# Copyright lowRISC contributors (OpenTitan project).
# Licensed under the Apache License, Version 2.0, see LICENSE for details.
# SPDX-License-Identifier: Apache-2.0
#
# This file was derived by lowRISC contributors (OpenTitan project) from the
# IHP Open PDK SRAM abstract RM_IHPSG13_1P_8192x32_c4.lef
# (https://github.com/IHP-GmbH/IHP-Open-PDK, ihp-sg13g2/libs.ref/sg13g2_sram/lef).
# It is a synthetic abstract, not an IHP release: the macro size and pins come
# from the Liberty view, the pin shapes, power straps and antenna values from
# the IHP abstract. IHP's original notice follows:
#
#   Copyright 2023 IHP PDK Authors
#
#   Licensed under the Apache License, Version 2.0 (the "License");
#   you may not use this file except in compliance with the License.
#   You may obtain a copy of the License at
#
#      https://www.apache.org/licenses/LICENSE-2.0
#
#   Unless required by applicable law or agreed to in writing, software
#   distributed under the License is distributed on an "AS IS" BASIS,
#   WITHOUT WARRANTIES OR CONDITIONS OF ANY KIND, either express or implied.
#   See the License for the specific language governing permissions and
#   limitations under the License.
#
#   Generated on Mon Apr  7 14:15:46 2025
#
# Generated by gen_synthetic_lef.py from the Liberty view. Do not edit.
# Synthetic abstract: no physical layout exists behind this macro.

VERSION 5.7 ;
BUSBITCHARS "[]" ;
DIVIDERCHAR "/" ;

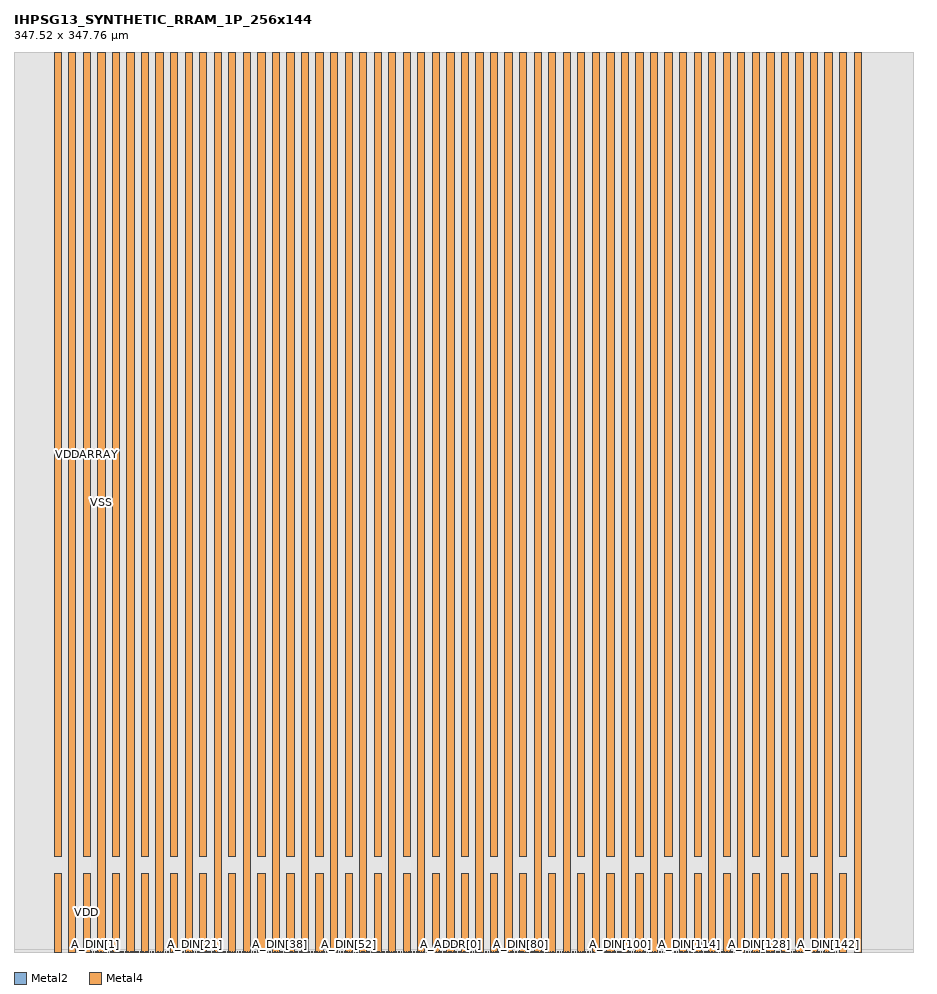
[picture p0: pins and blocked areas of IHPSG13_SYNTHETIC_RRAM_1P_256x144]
MACRO IHPSG13_SYNTHETIC_RRAM_1P_256x144
  CLASS BLOCK ;
  ORIGIN 0 0 ;
  FOREIGN IHPSG13_SYNTHETIC_RRAM_1P_256x144 0 0 ;
  SIZE 347.52 BY 347.76 ;
  SYMMETRY X Y R90 ;
  PIN A_DIN[0]
    DIRECTION INPUT ;
    USE SIGNAL ;
    ANTENNAMODEL OXIDE1 ;
      ANTENNAGATEAREA 0.20085 LAYER Metal2 ;
    PORT
      LAYER Metal2 ;
        RECT 29.63 0 29.89 0.26 ;
    END
  END A_DIN[0]
  PIN A_DOUT[0]
    DIRECTION OUTPUT ;
    USE SIGNAL ;
    ANTENNADIFFAREA 0.988 LAYER Metal2 ;
    PORT
      LAYER Metal2 ;
        RECT 30.59 0 30.85 0.26 ;
    END
  END A_DOUT[0]
  PIN A_DIN[1]
    DIRECTION INPUT ;
    USE SIGNAL ;
    ANTENNAMODEL OXIDE1 ;
      ANTENNAGATEAREA 0.20085 LAYER Metal2 ;
    PORT
      LAYER Metal2 ;
        RECT 31.55 0 31.81 0.26 ;
    END
  END A_DIN[1]
  PIN A_DOUT[1]
    DIRECTION OUTPUT ;
    USE SIGNAL ;
    ANTENNADIFFAREA 0.988 LAYER Metal2 ;
    PORT
      LAYER Metal2 ;
        RECT 32.51 0 32.77 0.26 ;
    END
  END A_DOUT[1]
  PIN A_DIN[2]
    DIRECTION INPUT ;
    USE SIGNAL ;
    ANTENNAMODEL OXIDE1 ;
      ANTENNAGATEAREA 0.20085 LAYER Metal2 ;
    PORT
      LAYER Metal2 ;
        RECT 33.47 0 33.73 0.26 ;
    END
  END A_DIN[2]
  PIN A_DOUT[2]
    DIRECTION OUTPUT ;
    USE SIGNAL ;
    ANTENNADIFFAREA 0.988 LAYER Metal2 ;
    PORT
      LAYER Metal2 ;
        RECT 34.43 0 34.69 0.26 ;
    END
  END A_DOUT[2]
  PIN A_DIN[3]
    DIRECTION INPUT ;
    USE SIGNAL ;
    ANTENNAMODEL OXIDE1 ;
      ANTENNAGATEAREA 0.20085 LAYER Metal2 ;
    PORT
      LAYER Metal2 ;
        RECT 35.39 0 35.65 0.26 ;
    END
  END A_DIN[3]
  PIN A_DOUT[3]
    DIRECTION OUTPUT ;
    USE SIGNAL ;
    ANTENNADIFFAREA 0.988 LAYER Metal2 ;
    PORT
      LAYER Metal2 ;
        RECT 36.35 0 36.61 0.26 ;
    END
  END A_DOUT[3]
  PIN A_DIN[4]
    DIRECTION INPUT ;
    USE SIGNAL ;
    ANTENNAMODEL OXIDE1 ;
      ANTENNAGATEAREA 0.20085 LAYER Metal2 ;
    PORT
      LAYER Metal2 ;
        RECT 37.31 0 37.57 0.26 ;
    END
  END A_DIN[4]
  PIN A_DOUT[4]
    DIRECTION OUTPUT ;
    USE SIGNAL ;
    ANTENNADIFFAREA 0.988 LAYER Metal2 ;
    PORT
      LAYER Metal2 ;
        RECT 38.27 0 38.53 0.26 ;
    END
  END A_DOUT[4]
  PIN A_DIN[5]
    DIRECTION INPUT ;
    USE SIGNAL ;
    ANTENNAMODEL OXIDE1 ;
      ANTENNAGATEAREA 0.20085 LAYER Metal2 ;
    PORT
      LAYER Metal2 ;
        RECT 39.23 0 39.49 0.26 ;
    END
  END A_DIN[5]
  PIN A_DOUT[5]
    DIRECTION OUTPUT ;
    USE SIGNAL ;
    ANTENNADIFFAREA 0.988 LAYER Metal2 ;
    PORT
      LAYER Metal2 ;
        RECT 40.19 0 40.45 0.26 ;
    END
  END A_DOUT[5]
  PIN A_DIN[6]
    DIRECTION INPUT ;
    USE SIGNAL ;
    ANTENNAMODEL OXIDE1 ;
      ANTENNAGATEAREA 0.20085 LAYER Metal2 ;
    PORT
      LAYER Metal2 ;
        RECT 41.15 0 41.41 0.26 ;
    END
  END A_DIN[6]
  PIN A_DOUT[6]
    DIRECTION OUTPUT ;
    USE SIGNAL ;
    ANTENNADIFFAREA 0.988 LAYER Metal2 ;
    PORT
      LAYER Metal2 ;
        RECT 42.11 0 42.37 0.26 ;
    END
  END A_DOUT[6]
  PIN A_DIN[7]
    DIRECTION INPUT ;
    USE SIGNAL ;
    ANTENNAMODEL OXIDE1 ;
      ANTENNAGATEAREA 0.20085 LAYER Metal2 ;
    PORT
      LAYER Metal2 ;
        RECT 43.07 0 43.33 0.26 ;
    END
  END A_DIN[7]
  PIN A_DOUT[7]
    DIRECTION OUTPUT ;
    USE SIGNAL ;
    ANTENNADIFFAREA 0.988 LAYER Metal2 ;
    PORT
      LAYER Metal2 ;
        RECT 44.03 0 44.29 0.26 ;
    END
  END A_DOUT[7]
  PIN A_DIN[8]
    DIRECTION INPUT ;
    USE SIGNAL ;
    ANTENNAMODEL OXIDE1 ;
      ANTENNAGATEAREA 0.20085 LAYER Metal2 ;
    PORT
      LAYER Metal2 ;
        RECT 44.99 0 45.25 0.26 ;
    END
  END A_DIN[8]
  PIN A_DOUT[8]
    DIRECTION OUTPUT ;
    USE SIGNAL ;
    ANTENNADIFFAREA 0.988 LAYER Metal2 ;
    PORT
      LAYER Metal2 ;
        RECT 45.95 0 46.21 0.26 ;
    END
  END A_DOUT[8]
  PIN A_DIN[9]
    DIRECTION INPUT ;
    USE SIGNAL ;
    ANTENNAMODEL OXIDE1 ;
      ANTENNAGATEAREA 0.20085 LAYER Metal2 ;
    PORT
      LAYER Metal2 ;
        RECT 46.91 0 47.17 0.26 ;
    END
  END A_DIN[9]
  PIN A_DOUT[9]
    DIRECTION OUTPUT ;
    USE SIGNAL ;
    ANTENNADIFFAREA 0.988 LAYER Metal2 ;
    PORT
      LAYER Metal2 ;
        RECT 47.87 0 48.13 0.26 ;
    END
  END A_DOUT[9]
  PIN A_DIN[10]
    DIRECTION INPUT ;
    USE SIGNAL ;
    ANTENNAMODEL OXIDE1 ;
      ANTENNAGATEAREA 0.20085 LAYER Metal2 ;
    PORT
      LAYER Metal2 ;
        RECT 48.83 0 49.09 0.26 ;
    END
  END A_DIN[10]
  PIN A_DOUT[10]
    DIRECTION OUTPUT ;
    USE SIGNAL ;
    ANTENNADIFFAREA 0.988 LAYER Metal2 ;
    PORT
      LAYER Metal2 ;
        RECT 49.79 0 50.05 0.26 ;
    END
  END A_DOUT[10]
  PIN A_DIN[11]
    DIRECTION INPUT ;
    USE SIGNAL ;
    ANTENNAMODEL OXIDE1 ;
      ANTENNAGATEAREA 0.20085 LAYER Metal2 ;
    PORT
      LAYER Metal2 ;
        RECT 50.75 0 51.01 0.26 ;
    END
  END A_DIN[11]
  PIN A_DOUT[11]
    DIRECTION OUTPUT ;
    USE SIGNAL ;
    ANTENNADIFFAREA 0.988 LAYER Metal2 ;
    PORT
      LAYER Metal2 ;
        RECT 51.71 0 51.97 0.26 ;
    END
  END A_DOUT[11]
  PIN A_DIN[12]
    DIRECTION INPUT ;
    USE SIGNAL ;
    ANTENNAMODEL OXIDE1 ;
      ANTENNAGATEAREA 0.20085 LAYER Metal2 ;
    PORT
      LAYER Metal2 ;
        RECT 52.67 0 52.93 0.26 ;
    END
  END A_DIN[12]
  PIN A_DOUT[12]
    DIRECTION OUTPUT ;
    USE SIGNAL ;
    ANTENNADIFFAREA 0.988 LAYER Metal2 ;
    PORT
      LAYER Metal2 ;
        RECT 53.63 0 53.89 0.26 ;
    END
  END A_DOUT[12]
  PIN A_DIN[13]
    DIRECTION INPUT ;
    USE SIGNAL ;
    ANTENNAMODEL OXIDE1 ;
      ANTENNAGATEAREA 0.20085 LAYER Metal2 ;
    PORT
      LAYER Metal2 ;
        RECT 54.59 0 54.85 0.26 ;
    END
  END A_DIN[13]
  PIN A_DOUT[13]
    DIRECTION OUTPUT ;
    USE SIGNAL ;
    ANTENNADIFFAREA 0.988 LAYER Metal2 ;
    PORT
      LAYER Metal2 ;
        RECT 55.55 0 55.81 0.26 ;
    END
  END A_DOUT[13]
  PIN A_DIN[14]
    DIRECTION INPUT ;
    USE SIGNAL ;
    ANTENNAMODEL OXIDE1 ;
      ANTENNAGATEAREA 0.20085 LAYER Metal2 ;
    PORT
      LAYER Metal2 ;
        RECT 56.51 0 56.77 0.26 ;
    END
  END A_DIN[14]
  PIN A_DOUT[14]
    DIRECTION OUTPUT ;
    USE SIGNAL ;
    ANTENNADIFFAREA 0.988 LAYER Metal2 ;
    PORT
      LAYER Metal2 ;
        RECT 57.47 0 57.73 0.26 ;
    END
  END A_DOUT[14]
  PIN A_DIN[15]
    DIRECTION INPUT ;
    USE SIGNAL ;
    ANTENNAMODEL OXIDE1 ;
      ANTENNAGATEAREA 0.20085 LAYER Metal2 ;
    PORT
      LAYER Metal2 ;
        RECT 58.43 0 58.69 0.26 ;
    END
  END A_DIN[15]
  PIN A_DOUT[15]
    DIRECTION OUTPUT ;
    USE SIGNAL ;
    ANTENNADIFFAREA 0.988 LAYER Metal2 ;
    PORT
      LAYER Metal2 ;
        RECT 59.39 0 59.65 0.26 ;
    END
  END A_DOUT[15]
  PIN A_DIN[16]
    DIRECTION INPUT ;
    USE SIGNAL ;
    ANTENNAMODEL OXIDE1 ;
      ANTENNAGATEAREA 0.20085 LAYER Metal2 ;
    PORT
      LAYER Metal2 ;
        RECT 60.35 0 60.61 0.26 ;
    END
  END A_DIN[16]
  PIN A_DOUT[16]
    DIRECTION OUTPUT ;
    USE SIGNAL ;
    ANTENNADIFFAREA 0.988 LAYER Metal2 ;
    PORT
      LAYER Metal2 ;
        RECT 61.31 0 61.57 0.26 ;
    END
  END A_DOUT[16]
  PIN A_DIN[17]
    DIRECTION INPUT ;
    USE SIGNAL ;
    ANTENNAMODEL OXIDE1 ;
      ANTENNAGATEAREA 0.20085 LAYER Metal2 ;
    PORT
      LAYER Metal2 ;
        RECT 62.27 0 62.53 0.26 ;
    END
  END A_DIN[17]
  PIN A_DOUT[17]
    DIRECTION OUTPUT ;
    USE SIGNAL ;
    ANTENNADIFFAREA 0.988 LAYER Metal2 ;
    PORT
      LAYER Metal2 ;
        RECT 63.23 0 63.49 0.26 ;
    END
  END A_DOUT[17]
  PIN A_DIN[18]
    DIRECTION INPUT ;
    USE SIGNAL ;
    ANTENNAMODEL OXIDE1 ;
      ANTENNAGATEAREA 0.20085 LAYER Metal2 ;
    PORT
      LAYER Metal2 ;
        RECT 64.19 0 64.45 0.26 ;
    END
  END A_DIN[18]
  PIN A_DOUT[18]
    DIRECTION OUTPUT ;
    USE SIGNAL ;
    ANTENNADIFFAREA 0.988 LAYER Metal2 ;
    PORT
      LAYER Metal2 ;
        RECT 65.15 0 65.41 0.26 ;
    END
  END A_DOUT[18]
  PIN A_DIN[19]
    DIRECTION INPUT ;
    USE SIGNAL ;
    ANTENNAMODEL OXIDE1 ;
      ANTENNAGATEAREA 0.20085 LAYER Metal2 ;
    PORT
      LAYER Metal2 ;
        RECT 66.11 0 66.37 0.26 ;
    END
  END A_DIN[19]
  PIN A_DOUT[19]
    DIRECTION OUTPUT ;
    USE SIGNAL ;
    ANTENNADIFFAREA 0.988 LAYER Metal2 ;
    PORT
      LAYER Metal2 ;
        RECT 67.07 0 67.33 0.26 ;
    END
  END A_DOUT[19]
  PIN A_DIN[20]
    DIRECTION INPUT ;
    USE SIGNAL ;
    ANTENNAMODEL OXIDE1 ;
      ANTENNAGATEAREA 0.20085 LAYER Metal2 ;
    PORT
      LAYER Metal2 ;
        RECT 68.03 0 68.29 0.26 ;
    END
  END A_DIN[20]
  PIN A_DOUT[20]
    DIRECTION OUTPUT ;
    USE SIGNAL ;
    ANTENNADIFFAREA 0.988 LAYER Metal2 ;
    PORT
      LAYER Metal2 ;
        RECT 68.99 0 69.25 0.26 ;
    END
  END A_DOUT[20]
  PIN A_DIN[21]
    DIRECTION INPUT ;
    USE SIGNAL ;
    ANTENNAMODEL OXIDE1 ;
      ANTENNAGATEAREA 0.20085 LAYER Metal2 ;
    PORT
      LAYER Metal2 ;
        RECT 69.95 0 70.21 0.26 ;
    END
  END A_DIN[21]
  PIN A_DOUT[21]
    DIRECTION OUTPUT ;
    USE SIGNAL ;
    ANTENNADIFFAREA 0.988 LAYER Metal2 ;
    PORT
      LAYER Metal2 ;
        RECT 70.91 0 71.17 0.26 ;
    END
  END A_DOUT[21]
  PIN A_DIN[22]
    DIRECTION INPUT ;
    USE SIGNAL ;
    ANTENNAMODEL OXIDE1 ;
      ANTENNAGATEAREA 0.20085 LAYER Metal2 ;
    PORT
      LAYER Metal2 ;
        RECT 71.87 0 72.13 0.26 ;
    END
  END A_DIN[22]
  PIN A_DOUT[22]
    DIRECTION OUTPUT ;
    USE SIGNAL ;
    ANTENNADIFFAREA 0.988 LAYER Metal2 ;
    PORT
      LAYER Metal2 ;
        RECT 72.83 0 73.09 0.26 ;
    END
  END A_DOUT[22]
  PIN A_DIN[23]
    DIRECTION INPUT ;
    USE SIGNAL ;
    ANTENNAMODEL OXIDE1 ;
      ANTENNAGATEAREA 0.20085 LAYER Metal2 ;
    PORT
      LAYER Metal2 ;
        RECT 73.79 0 74.05 0.26 ;
    END
  END A_DIN[23]
  PIN A_DOUT[23]
    DIRECTION OUTPUT ;
    USE SIGNAL ;
    ANTENNADIFFAREA 0.988 LAYER Metal2 ;
    PORT
      LAYER Metal2 ;
        RECT 74.75 0 75.01 0.26 ;
    END
  END A_DOUT[23]
  PIN A_DIN[24]
    DIRECTION INPUT ;
    USE SIGNAL ;
    ANTENNAMODEL OXIDE1 ;
      ANTENNAGATEAREA 0.20085 LAYER Metal2 ;
    PORT
      LAYER Metal2 ;
        RECT 75.71 0 75.97 0.26 ;
    END
  END A_DIN[24]
  PIN A_DOUT[24]
    DIRECTION OUTPUT ;
    USE SIGNAL ;
    ANTENNADIFFAREA 0.988 LAYER Metal2 ;
    PORT
      LAYER Metal2 ;
        RECT 76.67 0 76.93 0.26 ;
    END
  END A_DOUT[24]
  PIN A_DIN[25]
    DIRECTION INPUT ;
    USE SIGNAL ;
    ANTENNAMODEL OXIDE1 ;
      ANTENNAGATEAREA 0.20085 LAYER Metal2 ;
    PORT
      LAYER Metal2 ;
        RECT 77.63 0 77.89 0.26 ;
    END
  END A_DIN[25]
  PIN A_DOUT[25]
    DIRECTION OUTPUT ;
    USE SIGNAL ;
    ANTENNADIFFAREA 0.988 LAYER Metal2 ;
    PORT
      LAYER Metal2 ;
        RECT 78.59 0 78.85 0.26 ;
    END
  END A_DOUT[25]
  PIN A_DIN[26]
    DIRECTION INPUT ;
    USE SIGNAL ;
    ANTENNAMODEL OXIDE1 ;
      ANTENNAGATEAREA 0.20085 LAYER Metal2 ;
    PORT
      LAYER Metal2 ;
        RECT 79.55 0 79.81 0.26 ;
    END
  END A_DIN[26]
  PIN A_DOUT[26]
    DIRECTION OUTPUT ;
    USE SIGNAL ;
    ANTENNADIFFAREA 0.988 LAYER Metal2 ;
    PORT
      LAYER Metal2 ;
        RECT 80.51 0 80.77 0.26 ;
    END
  END A_DOUT[26]
  PIN A_DIN[27]
    DIRECTION INPUT ;
    USE SIGNAL ;
    ANTENNAMODEL OXIDE1 ;
      ANTENNAGATEAREA 0.20085 LAYER Metal2 ;
    PORT
      LAYER Metal2 ;
        RECT 81.47 0 81.73 0.26 ;
    END
  END A_DIN[27]
  PIN A_DOUT[27]
    DIRECTION OUTPUT ;
    USE SIGNAL ;
    ANTENNADIFFAREA 0.988 LAYER Metal2 ;
    PORT
      LAYER Metal2 ;
        RECT 82.43 0 82.69 0.26 ;
    END
  END A_DOUT[27]
  PIN A_DIN[28]
    DIRECTION INPUT ;
    USE SIGNAL ;
    ANTENNAMODEL OXIDE1 ;
      ANTENNAGATEAREA 0.20085 LAYER Metal2 ;
    PORT
      LAYER Metal2 ;
        RECT 83.39 0 83.65 0.26 ;
    END
  END A_DIN[28]
  PIN A_DOUT[28]
    DIRECTION OUTPUT ;
    USE SIGNAL ;
    ANTENNADIFFAREA 0.988 LAYER Metal2 ;
    PORT
      LAYER Metal2 ;
        RECT 84.35 0 84.61 0.26 ;
    END
  END A_DOUT[28]
  PIN A_DIN[29]
    DIRECTION INPUT ;
    USE SIGNAL ;
    ANTENNAMODEL OXIDE1 ;
      ANTENNAGATEAREA 0.20085 LAYER Metal2 ;
    PORT
      LAYER Metal2 ;
        RECT 85.31 0 85.57 0.26 ;
    END
  END A_DIN[29]
  PIN A_DOUT[29]
    DIRECTION OUTPUT ;
    USE SIGNAL ;
    ANTENNADIFFAREA 0.988 LAYER Metal2 ;
    PORT
      LAYER Metal2 ;
        RECT 86.27 0 86.53 0.26 ;
    END
  END A_DOUT[29]
  PIN A_DIN[30]
    DIRECTION INPUT ;
    USE SIGNAL ;
    ANTENNAMODEL OXIDE1 ;
      ANTENNAGATEAREA 0.20085 LAYER Metal2 ;
    PORT
      LAYER Metal2 ;
        RECT 87.23 0 87.49 0.26 ;
    END
  END A_DIN[30]
  PIN A_DOUT[30]
    DIRECTION OUTPUT ;
    USE SIGNAL ;
    ANTENNADIFFAREA 0.988 LAYER Metal2 ;
    PORT
      LAYER Metal2 ;
        RECT 88.19 0 88.45 0.26 ;
    END
  END A_DOUT[30]
  PIN A_DIN[31]
    DIRECTION INPUT ;
    USE SIGNAL ;
    ANTENNAMODEL OXIDE1 ;
      ANTENNAGATEAREA 0.20085 LAYER Metal2 ;
    PORT
      LAYER Metal2 ;
        RECT 89.15 0 89.41 0.26 ;
    END
  END A_DIN[31]
  PIN A_DOUT[31]
    DIRECTION OUTPUT ;
    USE SIGNAL ;
    ANTENNADIFFAREA 0.988 LAYER Metal2 ;
    PORT
      LAYER Metal2 ;
        RECT 90.11 0 90.37 0.26 ;
    END
  END A_DOUT[31]
  PIN A_DIN[32]
    DIRECTION INPUT ;
    USE SIGNAL ;
    ANTENNAMODEL OXIDE1 ;
      ANTENNAGATEAREA 0.20085 LAYER Metal2 ;
    PORT
      LAYER Metal2 ;
        RECT 91.07 0 91.33 0.26 ;
    END
  END A_DIN[32]
  PIN A_DOUT[32]
    DIRECTION OUTPUT ;
    USE SIGNAL ;
    ANTENNADIFFAREA 0.988 LAYER Metal2 ;
    PORT
      LAYER Metal2 ;
        RECT 92.03 0 92.29 0.26 ;
    END
  END A_DOUT[32]
  PIN A_DIN[33]
    DIRECTION INPUT ;
    USE SIGNAL ;
    ANTENNAMODEL OXIDE1 ;
      ANTENNAGATEAREA 0.20085 LAYER Metal2 ;
    PORT
      LAYER Metal2 ;
        RECT 92.99 0 93.25 0.26 ;
    END
  END A_DIN[33]
  PIN A_DOUT[33]
    DIRECTION OUTPUT ;
    USE SIGNAL ;
    ANTENNADIFFAREA 0.988 LAYER Metal2 ;
    PORT
      LAYER Metal2 ;
        RECT 93.95 0 94.21 0.26 ;
    END
  END A_DOUT[33]
  PIN A_DIN[34]
    DIRECTION INPUT ;
    USE SIGNAL ;
    ANTENNAMODEL OXIDE1 ;
      ANTENNAGATEAREA 0.20085 LAYER Metal2 ;
    PORT
      LAYER Metal2 ;
        RECT 94.91 0 95.17 0.26 ;
    END
  END A_DIN[34]
  PIN A_DOUT[34]
    DIRECTION OUTPUT ;
    USE SIGNAL ;
    ANTENNADIFFAREA 0.988 LAYER Metal2 ;
    PORT
      LAYER Metal2 ;
        RECT 95.87 0 96.13 0.26 ;
    END
  END A_DOUT[34]
  PIN A_DIN[35]
    DIRECTION INPUT ;
    USE SIGNAL ;
    ANTENNAMODEL OXIDE1 ;
      ANTENNAGATEAREA 0.20085 LAYER Metal2 ;
    PORT
      LAYER Metal2 ;
        RECT 96.83 0 97.09 0.26 ;
    END
  END A_DIN[35]
  PIN A_DOUT[35]
    DIRECTION OUTPUT ;
    USE SIGNAL ;
    ANTENNADIFFAREA 0.988 LAYER Metal2 ;
    PORT
      LAYER Metal2 ;
        RECT 97.79 0 98.05 0.26 ;
    END
  END A_DOUT[35]
  PIN A_DIN[36]
    DIRECTION INPUT ;
    USE SIGNAL ;
    ANTENNAMODEL OXIDE1 ;
      ANTENNAGATEAREA 0.20085 LAYER Metal2 ;
    PORT
      LAYER Metal2 ;
        RECT 98.75 0 99.01 0.26 ;
    END
  END A_DIN[36]
  PIN A_DOUT[36]
    DIRECTION OUTPUT ;
    USE SIGNAL ;
    ANTENNADIFFAREA 0.988 LAYER Metal2 ;
    PORT
      LAYER Metal2 ;
        RECT 99.71 0 99.97 0.26 ;
    END
  END A_DOUT[36]
  PIN A_DIN[37]
    DIRECTION INPUT ;
    USE SIGNAL ;
    ANTENNAMODEL OXIDE1 ;
      ANTENNAGATEAREA 0.20085 LAYER Metal2 ;
    PORT
      LAYER Metal2 ;
        RECT 100.67 0 100.93 0.26 ;
    END
  END A_DIN[37]
  PIN A_DOUT[37]
    DIRECTION OUTPUT ;
    USE SIGNAL ;
    ANTENNADIFFAREA 0.988 LAYER Metal2 ;
    PORT
      LAYER Metal2 ;
        RECT 101.63 0 101.89 0.26 ;
    END
  END A_DOUT[37]
  PIN A_DIN[38]
    DIRECTION INPUT ;
    USE SIGNAL ;
    ANTENNAMODEL OXIDE1 ;
      ANTENNAGATEAREA 0.20085 LAYER Metal2 ;
    PORT
      LAYER Metal2 ;
        RECT 102.59 0 102.85 0.26 ;
    END
  END A_DIN[38]
  PIN A_DOUT[38]
    DIRECTION OUTPUT ;
    USE SIGNAL ;
    ANTENNADIFFAREA 0.988 LAYER Metal2 ;
    PORT
      LAYER Metal2 ;
        RECT 103.55 0 103.81 0.26 ;
    END
  END A_DOUT[38]
  PIN A_DIN[39]
    DIRECTION INPUT ;
    USE SIGNAL ;
    ANTENNAMODEL OXIDE1 ;
      ANTENNAGATEAREA 0.20085 LAYER Metal2 ;
    PORT
      LAYER Metal2 ;
        RECT 104.51 0 104.77 0.26 ;
    END
  END A_DIN[39]
  PIN A_DOUT[39]
    DIRECTION OUTPUT ;
    USE SIGNAL ;
    ANTENNADIFFAREA 0.988 LAYER Metal2 ;
    PORT
      LAYER Metal2 ;
        RECT 105.47 0 105.73 0.26 ;
    END
  END A_DOUT[39]
  PIN A_DIN[40]
    DIRECTION INPUT ;
    USE SIGNAL ;
    ANTENNAMODEL OXIDE1 ;
      ANTENNAGATEAREA 0.20085 LAYER Metal2 ;
    PORT
      LAYER Metal2 ;
        RECT 106.43 0 106.69 0.26 ;
    END
  END A_DIN[40]
  PIN A_DOUT[40]
    DIRECTION OUTPUT ;
    USE SIGNAL ;
    ANTENNADIFFAREA 0.988 LAYER Metal2 ;
    PORT
      LAYER Metal2 ;
        RECT 107.39 0 107.65 0.26 ;
    END
  END A_DOUT[40]
  PIN A_DIN[41]
    DIRECTION INPUT ;
    USE SIGNAL ;
    ANTENNAMODEL OXIDE1 ;
      ANTENNAGATEAREA 0.20085 LAYER Metal2 ;
    PORT
      LAYER Metal2 ;
        RECT 108.35 0 108.61 0.26 ;
    END
  END A_DIN[41]
  PIN A_DOUT[41]
    DIRECTION OUTPUT ;
    USE SIGNAL ;
    ANTENNADIFFAREA 0.988 LAYER Metal2 ;
    PORT
      LAYER Metal2 ;
        RECT 109.31 0 109.57 0.26 ;
    END
  END A_DOUT[41]
  PIN A_DIN[42]
    DIRECTION INPUT ;
    USE SIGNAL ;
    ANTENNAMODEL OXIDE1 ;
      ANTENNAGATEAREA 0.20085 LAYER Metal2 ;
    PORT
      LAYER Metal2 ;
        RECT 110.27 0 110.53 0.26 ;
    END
  END A_DIN[42]
  PIN A_DOUT[42]
    DIRECTION OUTPUT ;
    USE SIGNAL ;
    ANTENNADIFFAREA 0.988 LAYER Metal2 ;
    PORT
      LAYER Metal2 ;
        RECT 111.23 0 111.49 0.26 ;
    END
  END A_DOUT[42]
  PIN A_DIN[43]
    DIRECTION INPUT ;
    USE SIGNAL ;
    ANTENNAMODEL OXIDE1 ;
      ANTENNAGATEAREA 0.20085 LAYER Metal2 ;
    PORT
      LAYER Metal2 ;
        RECT 112.19 0 112.45 0.26 ;
    END
  END A_DIN[43]
  PIN A_DOUT[43]
    DIRECTION OUTPUT ;
    USE SIGNAL ;
    ANTENNADIFFAREA 0.988 LAYER Metal2 ;
    PORT
      LAYER Metal2 ;
        RECT 113.15 0 113.41 0.26 ;
    END
  END A_DOUT[43]
  PIN A_DIN[44]
    DIRECTION INPUT ;
    USE SIGNAL ;
    ANTENNAMODEL OXIDE1 ;
      ANTENNAGATEAREA 0.20085 LAYER Metal2 ;
    PORT
      LAYER Metal2 ;
        RECT 114.11 0 114.37 0.26 ;
    END
  END A_DIN[44]
  PIN A_DOUT[44]
    DIRECTION OUTPUT ;
    USE SIGNAL ;
    ANTENNADIFFAREA 0.988 LAYER Metal2 ;
    PORT
      LAYER Metal2 ;
        RECT 115.07 0 115.33 0.26 ;
    END
  END A_DOUT[44]
  PIN A_DIN[45]
    DIRECTION INPUT ;
    USE SIGNAL ;
    ANTENNAMODEL OXIDE1 ;
      ANTENNAGATEAREA 0.20085 LAYER Metal2 ;
    PORT
      LAYER Metal2 ;
        RECT 116.03 0 116.29 0.26 ;
    END
  END A_DIN[45]
  PIN A_DOUT[45]
    DIRECTION OUTPUT ;
    USE SIGNAL ;
    ANTENNADIFFAREA 0.988 LAYER Metal2 ;
    PORT
      LAYER Metal2 ;
        RECT 116.99 0 117.25 0.26 ;
    END
  END A_DOUT[45]
  PIN A_DIN[46]
    DIRECTION INPUT ;
    USE SIGNAL ;
    ANTENNAMODEL OXIDE1 ;
      ANTENNAGATEAREA 0.20085 LAYER Metal2 ;
    PORT
      LAYER Metal2 ;
        RECT 117.95 0 118.21 0.26 ;
    END
  END A_DIN[46]
  PIN A_DOUT[46]
    DIRECTION OUTPUT ;
    USE SIGNAL ;
    ANTENNADIFFAREA 0.988 LAYER Metal2 ;
    PORT
      LAYER Metal2 ;
        RECT 118.91 0 119.17 0.26 ;
    END
  END A_DOUT[46]
  PIN A_DIN[47]
    DIRECTION INPUT ;
    USE SIGNAL ;
    ANTENNAMODEL OXIDE1 ;
      ANTENNAGATEAREA 0.20085 LAYER Metal2 ;
    PORT
      LAYER Metal2 ;
        RECT 119.87 0 120.13 0.26 ;
    END
  END A_DIN[47]
  PIN A_DOUT[47]
    DIRECTION OUTPUT ;
    USE SIGNAL ;
    ANTENNADIFFAREA 0.988 LAYER Metal2 ;
    PORT
      LAYER Metal2 ;
        RECT 120.83 0 121.09 0.26 ;
    END
  END A_DOUT[47]
  PIN A_DIN[48]
    DIRECTION INPUT ;
    USE SIGNAL ;
    ANTENNAMODEL OXIDE1 ;
      ANTENNAGATEAREA 0.20085 LAYER Metal2 ;
    PORT
      LAYER Metal2 ;
        RECT 121.79 0 122.05 0.26 ;
    END
  END A_DIN[48]
  PIN A_DOUT[48]
    DIRECTION OUTPUT ;
    USE SIGNAL ;
    ANTENNADIFFAREA 0.988 LAYER Metal2 ;
    PORT
      LAYER Metal2 ;
        RECT 122.75 0 123.01 0.26 ;
    END
  END A_DOUT[48]
  PIN A_DIN[49]
    DIRECTION INPUT ;
    USE SIGNAL ;
    ANTENNAMODEL OXIDE1 ;
      ANTENNAGATEAREA 0.20085 LAYER Metal2 ;
    PORT
      LAYER Metal2 ;
        RECT 123.71 0 123.97 0.26 ;
    END
  END A_DIN[49]
  PIN A_DOUT[49]
    DIRECTION OUTPUT ;
    USE SIGNAL ;
    ANTENNADIFFAREA 0.988 LAYER Metal2 ;
    PORT
      LAYER Metal2 ;
        RECT 124.67 0 124.93 0.26 ;
    END
  END A_DOUT[49]
  PIN A_DIN[50]
    DIRECTION INPUT ;
    USE SIGNAL ;
    ANTENNAMODEL OXIDE1 ;
      ANTENNAGATEAREA 0.20085 LAYER Metal2 ;
    PORT
      LAYER Metal2 ;
        RECT 125.63 0 125.89 0.26 ;
    END
  END A_DIN[50]
  PIN A_DOUT[50]
    DIRECTION OUTPUT ;
    USE SIGNAL ;
    ANTENNADIFFAREA 0.988 LAYER Metal2 ;
    PORT
      LAYER Metal2 ;
        RECT 126.59 0 126.85 0.26 ;
    END
  END A_DOUT[50]
  PIN A_DIN[51]
    DIRECTION INPUT ;
    USE SIGNAL ;
    ANTENNAMODEL OXIDE1 ;
      ANTENNAGATEAREA 0.20085 LAYER Metal2 ;
    PORT
      LAYER Metal2 ;
        RECT 127.55 0 127.81 0.26 ;
    END
  END A_DIN[51]
  PIN A_DOUT[51]
    DIRECTION OUTPUT ;
    USE SIGNAL ;
    ANTENNADIFFAREA 0.988 LAYER Metal2 ;
    PORT
      LAYER Metal2 ;
        RECT 128.51 0 128.77 0.26 ;
    END
  END A_DOUT[51]
  PIN A_DIN[52]
    DIRECTION INPUT ;
    USE SIGNAL ;
    ANTENNAMODEL OXIDE1 ;
      ANTENNAGATEAREA 0.20085 LAYER Metal2 ;
    PORT
      LAYER Metal2 ;
        RECT 129.47 0 129.73 0.26 ;
    END
  END A_DIN[52]
  PIN A_DOUT[52]
    DIRECTION OUTPUT ;
    USE SIGNAL ;
    ANTENNADIFFAREA 0.988 LAYER Metal2 ;
    PORT
      LAYER Metal2 ;
        RECT 130.43 0 130.69 0.26 ;
    END
  END A_DOUT[52]
  PIN A_DIN[53]
    DIRECTION INPUT ;
    USE SIGNAL ;
    ANTENNAMODEL OXIDE1 ;
      ANTENNAGATEAREA 0.20085 LAYER Metal2 ;
    PORT
      LAYER Metal2 ;
        RECT 131.39 0 131.65 0.26 ;
    END
  END A_DIN[53]
  PIN A_DOUT[53]
    DIRECTION OUTPUT ;
    USE SIGNAL ;
    ANTENNADIFFAREA 0.988 LAYER Metal2 ;
    PORT
      LAYER Metal2 ;
        RECT 132.35 0 132.61 0.26 ;
    END
  END A_DOUT[53]
  PIN A_DIN[54]
    DIRECTION INPUT ;
    USE SIGNAL ;
    ANTENNAMODEL OXIDE1 ;
      ANTENNAGATEAREA 0.20085 LAYER Metal2 ;
    PORT
      LAYER Metal2 ;
        RECT 133.31 0 133.57 0.26 ;
    END
  END A_DIN[54]
  PIN A_DOUT[54]
    DIRECTION OUTPUT ;
    USE SIGNAL ;
    ANTENNADIFFAREA 0.988 LAYER Metal2 ;
    PORT
      LAYER Metal2 ;
        RECT 134.27 0 134.53 0.26 ;
    END
  END A_DOUT[54]
  PIN A_DIN[55]
    DIRECTION INPUT ;
    USE SIGNAL ;
    ANTENNAMODEL OXIDE1 ;
      ANTENNAGATEAREA 0.20085 LAYER Metal2 ;
    PORT
      LAYER Metal2 ;
        RECT 135.23 0 135.49 0.26 ;
    END
  END A_DIN[55]
  PIN A_DOUT[55]
    DIRECTION OUTPUT ;
    USE SIGNAL ;
    ANTENNADIFFAREA 0.988 LAYER Metal2 ;
    PORT
      LAYER Metal2 ;
        RECT 136.19 0 136.45 0.26 ;
    END
  END A_DOUT[55]
  PIN A_DIN[56]
    DIRECTION INPUT ;
    USE SIGNAL ;
    ANTENNAMODEL OXIDE1 ;
      ANTENNAGATEAREA 0.20085 LAYER Metal2 ;
    PORT
      LAYER Metal2 ;
        RECT 137.15 0 137.41 0.26 ;
    END
  END A_DIN[56]
  PIN A_DOUT[56]
    DIRECTION OUTPUT ;
    USE SIGNAL ;
    ANTENNADIFFAREA 0.988 LAYER Metal2 ;
    PORT
      LAYER Metal2 ;
        RECT 138.11 0 138.37 0.26 ;
    END
  END A_DOUT[56]
  PIN A_DIN[57]
    DIRECTION INPUT ;
    USE SIGNAL ;
    ANTENNAMODEL OXIDE1 ;
      ANTENNAGATEAREA 0.20085 LAYER Metal2 ;
    PORT
      LAYER Metal2 ;
        RECT 139.07 0 139.33 0.26 ;
    END
  END A_DIN[57]
  PIN A_DOUT[57]
    DIRECTION OUTPUT ;
    USE SIGNAL ;
    ANTENNADIFFAREA 0.988 LAYER Metal2 ;
    PORT
      LAYER Metal2 ;
        RECT 140.03 0 140.29 0.26 ;
    END
  END A_DOUT[57]
  PIN A_DIN[58]
    DIRECTION INPUT ;
    USE SIGNAL ;
    ANTENNAMODEL OXIDE1 ;
      ANTENNAGATEAREA 0.20085 LAYER Metal2 ;
    PORT
      LAYER Metal2 ;
        RECT 140.99 0 141.25 0.26 ;
    END
  END A_DIN[58]
  PIN A_DOUT[58]
    DIRECTION OUTPUT ;
    USE SIGNAL ;
    ANTENNADIFFAREA 0.988 LAYER Metal2 ;
    PORT
      LAYER Metal2 ;
        RECT 141.95 0 142.21 0.26 ;
    END
  END A_DOUT[58]
  PIN A_DIN[59]
    DIRECTION INPUT ;
    USE SIGNAL ;
    ANTENNAMODEL OXIDE1 ;
      ANTENNAGATEAREA 0.20085 LAYER Metal2 ;
    PORT
      LAYER Metal2 ;
        RECT 142.91 0 143.17 0.26 ;
    END
  END A_DIN[59]
  PIN A_DOUT[59]
    DIRECTION OUTPUT ;
    USE SIGNAL ;
    ANTENNADIFFAREA 0.988 LAYER Metal2 ;
    PORT
      LAYER Metal2 ;
        RECT 143.87 0 144.13 0.26 ;
    END
  END A_DOUT[59]
  PIN A_DIN[60]
    DIRECTION INPUT ;
    USE SIGNAL ;
    ANTENNAMODEL OXIDE1 ;
      ANTENNAGATEAREA 0.20085 LAYER Metal2 ;
    PORT
      LAYER Metal2 ;
        RECT 144.83 0 145.09 0.26 ;
    END
  END A_DIN[60]
  PIN A_DOUT[60]
    DIRECTION OUTPUT ;
    USE SIGNAL ;
    ANTENNADIFFAREA 0.988 LAYER Metal2 ;
    PORT
      LAYER Metal2 ;
        RECT 145.79 0 146.05 0.26 ;
    END
  END A_DOUT[60]
  PIN A_DIN[61]
    DIRECTION INPUT ;
    USE SIGNAL ;
    ANTENNAMODEL OXIDE1 ;
      ANTENNAGATEAREA 0.20085 LAYER Metal2 ;
    PORT
      LAYER Metal2 ;
        RECT 146.75 0 147.01 0.26 ;
    END
  END A_DIN[61]
  PIN A_DOUT[61]
    DIRECTION OUTPUT ;
    USE SIGNAL ;
    ANTENNADIFFAREA 0.988 LAYER Metal2 ;
    PORT
      LAYER Metal2 ;
        RECT 147.71 0 147.97 0.26 ;
    END
  END A_DOUT[61]
  PIN A_DIN[62]
    DIRECTION INPUT ;
    USE SIGNAL ;
    ANTENNAMODEL OXIDE1 ;
      ANTENNAGATEAREA 0.20085 LAYER Metal2 ;
    PORT
      LAYER Metal2 ;
        RECT 148.67 0 148.93 0.26 ;
    END
  END A_DIN[62]
  PIN A_DOUT[62]
    DIRECTION OUTPUT ;
    USE SIGNAL ;
    ANTENNADIFFAREA 0.988 LAYER Metal2 ;
    PORT
      LAYER Metal2 ;
        RECT 149.63 0 149.89 0.26 ;
    END
  END A_DOUT[62]
  PIN A_DIN[63]
    DIRECTION INPUT ;
    USE SIGNAL ;
    ANTENNAMODEL OXIDE1 ;
      ANTENNAGATEAREA 0.20085 LAYER Metal2 ;
    PORT
      LAYER Metal2 ;
        RECT 150.59 0 150.85 0.26 ;
    END
  END A_DIN[63]
  PIN A_DOUT[63]
    DIRECTION OUTPUT ;
    USE SIGNAL ;
    ANTENNADIFFAREA 0.988 LAYER Metal2 ;
    PORT
      LAYER Metal2 ;
        RECT 151.55 0 151.81 0.26 ;
    END
  END A_DOUT[63]
  PIN A_DIN[64]
    DIRECTION INPUT ;
    USE SIGNAL ;
    ANTENNAMODEL OXIDE1 ;
      ANTENNAGATEAREA 0.20085 LAYER Metal2 ;
    PORT
      LAYER Metal2 ;
        RECT 152.51 0 152.77 0.26 ;
    END
  END A_DIN[64]
  PIN A_DOUT[64]
    DIRECTION OUTPUT ;
    USE SIGNAL ;
    ANTENNADIFFAREA 0.988 LAYER Metal2 ;
    PORT
      LAYER Metal2 ;
        RECT 153.47 0 153.73 0.26 ;
    END
  END A_DOUT[64]
  PIN A_DIN[65]
    DIRECTION INPUT ;
    USE SIGNAL ;
    ANTENNAMODEL OXIDE1 ;
      ANTENNAGATEAREA 0.20085 LAYER Metal2 ;
    PORT
      LAYER Metal2 ;
        RECT 154.43 0 154.69 0.26 ;
    END
  END A_DIN[65]
  PIN A_DOUT[65]
    DIRECTION OUTPUT ;
    USE SIGNAL ;
    ANTENNADIFFAREA 0.988 LAYER Metal2 ;
    PORT
      LAYER Metal2 ;
        RECT 155.39 0 155.65 0.26 ;
    END
  END A_DOUT[65]
  PIN A_DIN[66]
    DIRECTION INPUT ;
    USE SIGNAL ;
    ANTENNAMODEL OXIDE1 ;
      ANTENNAGATEAREA 0.20085 LAYER Metal2 ;
    PORT
      LAYER Metal2 ;
        RECT 156.35 0 156.61 0.26 ;
    END
  END A_DIN[66]
  PIN A_DOUT[66]
    DIRECTION OUTPUT ;
    USE SIGNAL ;
    ANTENNADIFFAREA 0.988 LAYER Metal2 ;
    PORT
      LAYER Metal2 ;
        RECT 157.31 0 157.57 0.26 ;
    END
  END A_DOUT[66]
  PIN A_DIN[67]
    DIRECTION INPUT ;
    USE SIGNAL ;
    ANTENNAMODEL OXIDE1 ;
      ANTENNAGATEAREA 0.20085 LAYER Metal2 ;
    PORT
      LAYER Metal2 ;
        RECT 158.27 0 158.53 0.26 ;
    END
  END A_DIN[67]
  PIN A_DOUT[67]
    DIRECTION OUTPUT ;
    USE SIGNAL ;
    ANTENNADIFFAREA 0.988 LAYER Metal2 ;
    PORT
      LAYER Metal2 ;
        RECT 159.23 0 159.49 0.26 ;
    END
  END A_DOUT[67]
  PIN A_DIN[68]
    DIRECTION INPUT ;
    USE SIGNAL ;
    ANTENNAMODEL OXIDE1 ;
      ANTENNAGATEAREA 0.20085 LAYER Metal2 ;
    PORT
      LAYER Metal2 ;
        RECT 160.19 0 160.45 0.26 ;
    END
  END A_DIN[68]
  PIN A_DOUT[68]
    DIRECTION OUTPUT ;
    USE SIGNAL ;
    ANTENNADIFFAREA 0.988 LAYER Metal2 ;
    PORT
      LAYER Metal2 ;
        RECT 161.15 0 161.41 0.26 ;
    END
  END A_DOUT[68]
  PIN A_DIN[69]
    DIRECTION INPUT ;
    USE SIGNAL ;
    ANTENNAMODEL OXIDE1 ;
      ANTENNAGATEAREA 0.20085 LAYER Metal2 ;
    PORT
      LAYER Metal2 ;
        RECT 162.11 0 162.37 0.26 ;
    END
  END A_DIN[69]
  PIN A_DOUT[69]
    DIRECTION OUTPUT ;
    USE SIGNAL ;
    ANTENNADIFFAREA 0.988 LAYER Metal2 ;
    PORT
      LAYER Metal2 ;
        RECT 163.07 0 163.33 0.26 ;
    END
  END A_DOUT[69]
  PIN A_DIN[70]
    DIRECTION INPUT ;
    USE SIGNAL ;
    ANTENNAMODEL OXIDE1 ;
      ANTENNAGATEAREA 0.20085 LAYER Metal2 ;
    PORT
      LAYER Metal2 ;
        RECT 164.03 0 164.29 0.26 ;
    END
  END A_DIN[70]
  PIN A_DOUT[70]
    DIRECTION OUTPUT ;
    USE SIGNAL ;
    ANTENNADIFFAREA 0.988 LAYER Metal2 ;
    PORT
      LAYER Metal2 ;
        RECT 164.99 0 165.25 0.26 ;
    END
  END A_DOUT[70]
  PIN A_DIN[71]
    DIRECTION INPUT ;
    USE SIGNAL ;
    ANTENNAMODEL OXIDE1 ;
      ANTENNAGATEAREA 0.20085 LAYER Metal2 ;
    PORT
      LAYER Metal2 ;
        RECT 165.95 0 166.21 0.26 ;
    END
  END A_DIN[71]
  PIN A_DOUT[71]
    DIRECTION OUTPUT ;
    USE SIGNAL ;
    ANTENNADIFFAREA 0.988 LAYER Metal2 ;
    PORT
      LAYER Metal2 ;
        RECT 166.91 0 167.17 0.26 ;
    END
  END A_DOUT[71]
  PIN A_DLY
    DIRECTION INPUT ;
    USE SIGNAL ;
    ANTENNAMODEL OXIDE1 ;
      ANTENNAGATEAREA 0.20085 LAYER Metal2 ;
    PORT
      LAYER Metal2 ;
        RECT 167.87 0 168.13 0.26 ;
    END
  END A_DLY
  PIN A_ADDR[0]
    DIRECTION INPUT ;
    USE SIGNAL ;
    ANTENNAMODEL OXIDE1 ;
      ANTENNAGATEAREA 0.20085 LAYER Metal2 ;
    PORT
      LAYER Metal2 ;
        RECT 168.83 0 169.09 0.26 ;
    END
  END A_ADDR[0]
  PIN A_ADDR[1]
    DIRECTION INPUT ;
    USE SIGNAL ;
    ANTENNAMODEL OXIDE1 ;
      ANTENNAGATEAREA 0.20085 LAYER Metal2 ;
    PORT
      LAYER Metal2 ;
        RECT 169.79 0 170.05 0.26 ;
    END
  END A_ADDR[1]
  PIN A_ADDR[2]
    DIRECTION INPUT ;
    USE SIGNAL ;
    ANTENNAMODEL OXIDE1 ;
      ANTENNAGATEAREA 0.20085 LAYER Metal2 ;
    PORT
      LAYER Metal2 ;
        RECT 170.75 0 171.01 0.26 ;
    END
  END A_ADDR[2]
  PIN A_ADDR[3]
    DIRECTION INPUT ;
    USE SIGNAL ;
    ANTENNAMODEL OXIDE1 ;
      ANTENNAGATEAREA 0.20085 LAYER Metal2 ;
    PORT
      LAYER Metal2 ;
        RECT 171.71 0 171.97 0.26 ;
    END
  END A_ADDR[3]
  PIN A_ADDR[4]
    DIRECTION INPUT ;
    USE SIGNAL ;
    ANTENNAMODEL OXIDE1 ;
      ANTENNAGATEAREA 0.20085 LAYER Metal2 ;
    PORT
      LAYER Metal2 ;
        RECT 172.67 0 172.93 0.26 ;
    END
  END A_ADDR[4]
  PIN A_ADDR[5]
    DIRECTION INPUT ;
    USE SIGNAL ;
    ANTENNAMODEL OXIDE1 ;
      ANTENNAGATEAREA 0.20085 LAYER Metal2 ;
    PORT
      LAYER Metal2 ;
        RECT 173.63 0 173.89 0.26 ;
    END
  END A_ADDR[5]
  PIN A_ADDR[6]
    DIRECTION INPUT ;
    USE SIGNAL ;
    ANTENNAMODEL OXIDE1 ;
      ANTENNAGATEAREA 0.20085 LAYER Metal2 ;
    PORT
      LAYER Metal2 ;
        RECT 174.59 0 174.85 0.26 ;
    END
  END A_ADDR[6]
  PIN A_ADDR[7]
    DIRECTION INPUT ;
    USE SIGNAL ;
    ANTENNAMODEL OXIDE1 ;
      ANTENNAGATEAREA 0.20085 LAYER Metal2 ;
    PORT
      LAYER Metal2 ;
        RECT 175.55 0 175.81 0.26 ;
    END
  END A_ADDR[7]
  PIN A_WEN
    DIRECTION INPUT ;
    USE SIGNAL ;
    ANTENNAMODEL OXIDE1 ;
      ANTENNAGATEAREA 0.20085 LAYER Metal2 ;
    PORT
      LAYER Metal2 ;
        RECT 176.51 0 176.77 0.26 ;
    END
  END A_WEN
  PIN A_REN
    DIRECTION INPUT ;
    USE SIGNAL ;
    ANTENNAMODEL OXIDE1 ;
      ANTENNAGATEAREA 0.20085 LAYER Metal2 ;
    PORT
      LAYER Metal2 ;
        RECT 177.47 0 177.73 0.26 ;
    END
  END A_REN
  PIN A_MEN
    DIRECTION INPUT ;
    USE SIGNAL ;
    ANTENNAMODEL OXIDE1 ;
      ANTENNAGATEAREA 0.20085 LAYER Metal2 ;
    PORT
      LAYER Metal2 ;
        RECT 178.43 0 178.69 0.26 ;
    END
  END A_MEN
  PIN A_CLK
    DIRECTION INPUT ;
    USE SIGNAL ;
    ANTENNAMODEL OXIDE1 ;
      ANTENNAGATEAREA 0.20085 LAYER Metal2 ;
    PORT
      LAYER Metal2 ;
        RECT 179.39 0 179.65 0.26 ;
    END
  END A_CLK
  PIN A_DIN[72]
    DIRECTION INPUT ;
    USE SIGNAL ;
    ANTENNAMODEL OXIDE1 ;
      ANTENNAGATEAREA 0.20085 LAYER Metal2 ;
    PORT
      LAYER Metal2 ;
        RECT 180.35 0 180.61 0.26 ;
    END
  END A_DIN[72]
  PIN A_DOUT[72]
    DIRECTION OUTPUT ;
    USE SIGNAL ;
    ANTENNADIFFAREA 0.988 LAYER Metal2 ;
    PORT
      LAYER Metal2 ;
        RECT 181.31 0 181.57 0.26 ;
    END
  END A_DOUT[72]
  PIN A_DIN[73]
    DIRECTION INPUT ;
    USE SIGNAL ;
    ANTENNAMODEL OXIDE1 ;
      ANTENNAGATEAREA 0.20085 LAYER Metal2 ;
    PORT
      LAYER Metal2 ;
        RECT 182.27 0 182.53 0.26 ;
    END
  END A_DIN[73]
  PIN A_DOUT[73]
    DIRECTION OUTPUT ;
    USE SIGNAL ;
    ANTENNADIFFAREA 0.988 LAYER Metal2 ;
    PORT
      LAYER Metal2 ;
        RECT 183.23 0 183.49 0.26 ;
    END
  END A_DOUT[73]
  PIN A_DIN[74]
    DIRECTION INPUT ;
    USE SIGNAL ;
    ANTENNAMODEL OXIDE1 ;
      ANTENNAGATEAREA 0.20085 LAYER Metal2 ;
    PORT
      LAYER Metal2 ;
        RECT 184.19 0 184.45 0.26 ;
    END
  END A_DIN[74]
  PIN A_DOUT[74]
    DIRECTION OUTPUT ;
    USE SIGNAL ;
    ANTENNADIFFAREA 0.988 LAYER Metal2 ;
    PORT
      LAYER Metal2 ;
        RECT 185.15 0 185.41 0.26 ;
    END
  END A_DOUT[74]
  PIN A_DIN[75]
    DIRECTION INPUT ;
    USE SIGNAL ;
    ANTENNAMODEL OXIDE1 ;
      ANTENNAGATEAREA 0.20085 LAYER Metal2 ;
    PORT
      LAYER Metal2 ;
        RECT 186.11 0 186.37 0.26 ;
    END
  END A_DIN[75]
  PIN A_DOUT[75]
    DIRECTION OUTPUT ;
    USE SIGNAL ;
    ANTENNADIFFAREA 0.988 LAYER Metal2 ;
    PORT
      LAYER Metal2 ;
        RECT 187.07 0 187.33 0.26 ;
    END
  END A_DOUT[75]
  PIN A_DIN[76]
    DIRECTION INPUT ;
    USE SIGNAL ;
    ANTENNAMODEL OXIDE1 ;
      ANTENNAGATEAREA 0.20085 LAYER Metal2 ;
    PORT
      LAYER Metal2 ;
        RECT 188.03 0 188.29 0.26 ;
    END
  END A_DIN[76]
  PIN A_DOUT[76]
    DIRECTION OUTPUT ;
    USE SIGNAL ;
    ANTENNADIFFAREA 0.988 LAYER Metal2 ;
    PORT
      LAYER Metal2 ;
        RECT 188.99 0 189.25 0.26 ;
    END
  END A_DOUT[76]
  PIN A_DIN[77]
    DIRECTION INPUT ;
    USE SIGNAL ;
    ANTENNAMODEL OXIDE1 ;
      ANTENNAGATEAREA 0.20085 LAYER Metal2 ;
    PORT
      LAYER Metal2 ;
        RECT 189.95 0 190.21 0.26 ;
    END
  END A_DIN[77]
  PIN A_DOUT[77]
    DIRECTION OUTPUT ;
    USE SIGNAL ;
    ANTENNADIFFAREA 0.988 LAYER Metal2 ;
    PORT
      LAYER Metal2 ;
        RECT 190.91 0 191.17 0.26 ;
    END
  END A_DOUT[77]
  PIN A_DIN[78]
    DIRECTION INPUT ;
    USE SIGNAL ;
    ANTENNAMODEL OXIDE1 ;
      ANTENNAGATEAREA 0.20085 LAYER Metal2 ;
    PORT
      LAYER Metal2 ;
        RECT 191.87 0 192.13 0.26 ;
    END
  END A_DIN[78]
  PIN A_DOUT[78]
    DIRECTION OUTPUT ;
    USE SIGNAL ;
    ANTENNADIFFAREA 0.988 LAYER Metal2 ;
    PORT
      LAYER Metal2 ;
        RECT 192.83 0 193.09 0.26 ;
    END
  END A_DOUT[78]
  PIN A_DIN[79]
    DIRECTION INPUT ;
    USE SIGNAL ;
    ANTENNAMODEL OXIDE1 ;
      ANTENNAGATEAREA 0.20085 LAYER Metal2 ;
    PORT
      LAYER Metal2 ;
        RECT 193.79 0 194.05 0.26 ;
    END
  END A_DIN[79]
  PIN A_DOUT[79]
    DIRECTION OUTPUT ;
    USE SIGNAL ;
    ANTENNADIFFAREA 0.988 LAYER Metal2 ;
    PORT
      LAYER Metal2 ;
        RECT 194.75 0 195.01 0.26 ;
    END
  END A_DOUT[79]
  PIN A_DIN[80]
    DIRECTION INPUT ;
    USE SIGNAL ;
    ANTENNAMODEL OXIDE1 ;
      ANTENNAGATEAREA 0.20085 LAYER Metal2 ;
    PORT
      LAYER Metal2 ;
        RECT 195.71 0 195.97 0.26 ;
    END
  END A_DIN[80]
  PIN A_DOUT[80]
    DIRECTION OUTPUT ;
    USE SIGNAL ;
    ANTENNADIFFAREA 0.988 LAYER Metal2 ;
    PORT
      LAYER Metal2 ;
        RECT 196.67 0 196.93 0.26 ;
    END
  END A_DOUT[80]
  PIN A_DIN[81]
    DIRECTION INPUT ;
    USE SIGNAL ;
    ANTENNAMODEL OXIDE1 ;
      ANTENNAGATEAREA 0.20085 LAYER Metal2 ;
    PORT
      LAYER Metal2 ;
        RECT 197.63 0 197.89 0.26 ;
    END
  END A_DIN[81]
  PIN A_DOUT[81]
    DIRECTION OUTPUT ;
    USE SIGNAL ;
    ANTENNADIFFAREA 0.988 LAYER Metal2 ;
    PORT
      LAYER Metal2 ;
        RECT 198.59 0 198.85 0.26 ;
    END
  END A_DOUT[81]
  PIN A_DIN[82]
    DIRECTION INPUT ;
    USE SIGNAL ;
    ANTENNAMODEL OXIDE1 ;
      ANTENNAGATEAREA 0.20085 LAYER Metal2 ;
    PORT
      LAYER Metal2 ;
        RECT 199.55 0 199.81 0.26 ;
    END
  END A_DIN[82]
  PIN A_DOUT[82]
    DIRECTION OUTPUT ;
    USE SIGNAL ;
    ANTENNADIFFAREA 0.988 LAYER Metal2 ;
    PORT
      LAYER Metal2 ;
        RECT 200.51 0 200.77 0.26 ;
    END
  END A_DOUT[82]
  PIN A_DIN[83]
    DIRECTION INPUT ;
    USE SIGNAL ;
    ANTENNAMODEL OXIDE1 ;
      ANTENNAGATEAREA 0.20085 LAYER Metal2 ;
    PORT
      LAYER Metal2 ;
        RECT 201.47 0 201.73 0.26 ;
    END
  END A_DIN[83]
  PIN A_DOUT[83]
    DIRECTION OUTPUT ;
    USE SIGNAL ;
    ANTENNADIFFAREA 0.988 LAYER Metal2 ;
    PORT
      LAYER Metal2 ;
        RECT 202.43 0 202.69 0.26 ;
    END
  END A_DOUT[83]
  PIN A_DIN[84]
    DIRECTION INPUT ;
    USE SIGNAL ;
    ANTENNAMODEL OXIDE1 ;
      ANTENNAGATEAREA 0.20085 LAYER Metal2 ;
    PORT
      LAYER Metal2 ;
        RECT 203.39 0 203.65 0.26 ;
    END
  END A_DIN[84]
  PIN A_DOUT[84]
    DIRECTION OUTPUT ;
    USE SIGNAL ;
    ANTENNADIFFAREA 0.988 LAYER Metal2 ;
    PORT
      LAYER Metal2 ;
        RECT 204.35 0 204.61 0.26 ;
    END
  END A_DOUT[84]
  PIN A_DIN[85]
    DIRECTION INPUT ;
    USE SIGNAL ;
    ANTENNAMODEL OXIDE1 ;
      ANTENNAGATEAREA 0.20085 LAYER Metal2 ;
    PORT
      LAYER Metal2 ;
        RECT 205.31 0 205.57 0.26 ;
    END
  END A_DIN[85]
  PIN A_DOUT[85]
    DIRECTION OUTPUT ;
    USE SIGNAL ;
    ANTENNADIFFAREA 0.988 LAYER Metal2 ;
    PORT
      LAYER Metal2 ;
        RECT 206.27 0 206.53 0.26 ;
    END
  END A_DOUT[85]
  PIN A_DIN[86]
    DIRECTION INPUT ;
    USE SIGNAL ;
    ANTENNAMODEL OXIDE1 ;
      ANTENNAGATEAREA 0.20085 LAYER Metal2 ;
    PORT
      LAYER Metal2 ;
        RECT 207.23 0 207.49 0.26 ;
    END
  END A_DIN[86]
  PIN A_DOUT[86]
    DIRECTION OUTPUT ;
    USE SIGNAL ;
    ANTENNADIFFAREA 0.988 LAYER Metal2 ;
    PORT
      LAYER Metal2 ;
        RECT 208.19 0 208.45 0.26 ;
    END
  END A_DOUT[86]
  PIN A_DIN[87]
    DIRECTION INPUT ;
    USE SIGNAL ;
    ANTENNAMODEL OXIDE1 ;
      ANTENNAGATEAREA 0.20085 LAYER Metal2 ;
    PORT
      LAYER Metal2 ;
        RECT 209.15 0 209.41 0.26 ;
    END
  END A_DIN[87]
  PIN A_DOUT[87]
    DIRECTION OUTPUT ;
    USE SIGNAL ;
    ANTENNADIFFAREA 0.988 LAYER Metal2 ;
    PORT
      LAYER Metal2 ;
        RECT 210.11 0 210.37 0.26 ;
    END
  END A_DOUT[87]
  PIN A_DIN[88]
    DIRECTION INPUT ;
    USE SIGNAL ;
    ANTENNAMODEL OXIDE1 ;
      ANTENNAGATEAREA 0.20085 LAYER Metal2 ;
    PORT
      LAYER Metal2 ;
        RECT 211.07 0 211.33 0.26 ;
    END
  END A_DIN[88]
  PIN A_DOUT[88]
    DIRECTION OUTPUT ;
    USE SIGNAL ;
    ANTENNADIFFAREA 0.988 LAYER Metal2 ;
    PORT
      LAYER Metal2 ;
        RECT 212.03 0 212.29 0.26 ;
    END
  END A_DOUT[88]
  PIN A_DIN[89]
    DIRECTION INPUT ;
    USE SIGNAL ;
    ANTENNAMODEL OXIDE1 ;
      ANTENNAGATEAREA 0.20085 LAYER Metal2 ;
    PORT
      LAYER Metal2 ;
        RECT 212.99 0 213.25 0.26 ;
    END
  END A_DIN[89]
  PIN A_DOUT[89]
    DIRECTION OUTPUT ;
    USE SIGNAL ;
    ANTENNADIFFAREA 0.988 LAYER Metal2 ;
    PORT
      LAYER Metal2 ;
        RECT 213.95 0 214.21 0.26 ;
    END
  END A_DOUT[89]
  PIN A_DIN[90]
    DIRECTION INPUT ;
    USE SIGNAL ;
    ANTENNAMODEL OXIDE1 ;
      ANTENNAGATEAREA 0.20085 LAYER Metal2 ;
    PORT
      LAYER Metal2 ;
        RECT 214.91 0 215.17 0.26 ;
    END
  END A_DIN[90]
  PIN A_DOUT[90]
    DIRECTION OUTPUT ;
    USE SIGNAL ;
    ANTENNADIFFAREA 0.988 LAYER Metal2 ;
    PORT
      LAYER Metal2 ;
        RECT 215.87 0 216.13 0.26 ;
    END
  END A_DOUT[90]
  PIN A_DIN[91]
    DIRECTION INPUT ;
    USE SIGNAL ;
    ANTENNAMODEL OXIDE1 ;
      ANTENNAGATEAREA 0.20085 LAYER Metal2 ;
    PORT
      LAYER Metal2 ;
        RECT 216.83 0 217.09 0.26 ;
    END
  END A_DIN[91]
  PIN A_DOUT[91]
    DIRECTION OUTPUT ;
    USE SIGNAL ;
    ANTENNADIFFAREA 0.988 LAYER Metal2 ;
    PORT
      LAYER Metal2 ;
        RECT 217.79 0 218.05 0.26 ;
    END
  END A_DOUT[91]
  PIN A_DIN[92]
    DIRECTION INPUT ;
    USE SIGNAL ;
    ANTENNAMODEL OXIDE1 ;
      ANTENNAGATEAREA 0.20085 LAYER Metal2 ;
    PORT
      LAYER Metal2 ;
        RECT 218.75 0 219.01 0.26 ;
    END
  END A_DIN[92]
  PIN A_DOUT[92]
    DIRECTION OUTPUT ;
    USE SIGNAL ;
    ANTENNADIFFAREA 0.988 LAYER Metal2 ;
    PORT
      LAYER Metal2 ;
        RECT 219.71 0 219.97 0.26 ;
    END
  END A_DOUT[92]
  PIN A_DIN[93]
    DIRECTION INPUT ;
    USE SIGNAL ;
    ANTENNAMODEL OXIDE1 ;
      ANTENNAGATEAREA 0.20085 LAYER Metal2 ;
    PORT
      LAYER Metal2 ;
        RECT 220.67 0 220.93 0.26 ;
    END
  END A_DIN[93]
  PIN A_DOUT[93]
    DIRECTION OUTPUT ;
    USE SIGNAL ;
    ANTENNADIFFAREA 0.988 LAYER Metal2 ;
    PORT
      LAYER Metal2 ;
        RECT 221.63 0 221.89 0.26 ;
    END
  END A_DOUT[93]
  PIN A_DIN[94]
    DIRECTION INPUT ;
    USE SIGNAL ;
    ANTENNAMODEL OXIDE1 ;
      ANTENNAGATEAREA 0.20085 LAYER Metal2 ;
    PORT
      LAYER Metal2 ;
        RECT 222.59 0 222.85 0.26 ;
    END
  END A_DIN[94]
  PIN A_DOUT[94]
    DIRECTION OUTPUT ;
    USE SIGNAL ;
    ANTENNADIFFAREA 0.988 LAYER Metal2 ;
    PORT
      LAYER Metal2 ;
        RECT 223.55 0 223.81 0.26 ;
    END
  END A_DOUT[94]
  PIN A_DIN[95]
    DIRECTION INPUT ;
    USE SIGNAL ;
    ANTENNAMODEL OXIDE1 ;
      ANTENNAGATEAREA 0.20085 LAYER Metal2 ;
    PORT
      LAYER Metal2 ;
        RECT 224.51 0 224.77 0.26 ;
    END
  END A_DIN[95]
  PIN A_DOUT[95]
    DIRECTION OUTPUT ;
    USE SIGNAL ;
    ANTENNADIFFAREA 0.988 LAYER Metal2 ;
    PORT
      LAYER Metal2 ;
        RECT 225.47 0 225.73 0.26 ;
    END
  END A_DOUT[95]
  PIN A_DIN[96]
    DIRECTION INPUT ;
    USE SIGNAL ;
    ANTENNAMODEL OXIDE1 ;
      ANTENNAGATEAREA 0.20085 LAYER Metal2 ;
    PORT
      LAYER Metal2 ;
        RECT 226.43 0 226.69 0.26 ;
    END
  END A_DIN[96]
  PIN A_DOUT[96]
    DIRECTION OUTPUT ;
    USE SIGNAL ;
    ANTENNADIFFAREA 0.988 LAYER Metal2 ;
    PORT
      LAYER Metal2 ;
        RECT 227.39 0 227.65 0.26 ;
    END
  END A_DOUT[96]
  PIN A_DIN[97]
    DIRECTION INPUT ;
    USE SIGNAL ;
    ANTENNAMODEL OXIDE1 ;
      ANTENNAGATEAREA 0.20085 LAYER Metal2 ;
    PORT
      LAYER Metal2 ;
        RECT 228.35 0 228.61 0.26 ;
    END
  END A_DIN[97]
  PIN A_DOUT[97]
    DIRECTION OUTPUT ;
    USE SIGNAL ;
    ANTENNADIFFAREA 0.988 LAYER Metal2 ;
    PORT
      LAYER Metal2 ;
        RECT 229.31 0 229.57 0.26 ;
    END
  END A_DOUT[97]
  PIN A_DIN[98]
    DIRECTION INPUT ;
    USE SIGNAL ;
    ANTENNAMODEL OXIDE1 ;
      ANTENNAGATEAREA 0.20085 LAYER Metal2 ;
    PORT
      LAYER Metal2 ;
        RECT 230.27 0 230.53 0.26 ;
    END
  END A_DIN[98]
  PIN A_DOUT[98]
    DIRECTION OUTPUT ;
    USE SIGNAL ;
    ANTENNADIFFAREA 0.988 LAYER Metal2 ;
    PORT
      LAYER Metal2 ;
        RECT 231.23 0 231.49 0.26 ;
    END
  END A_DOUT[98]
  PIN A_DIN[99]
    DIRECTION INPUT ;
    USE SIGNAL ;
    ANTENNAMODEL OXIDE1 ;
      ANTENNAGATEAREA 0.20085 LAYER Metal2 ;
    PORT
      LAYER Metal2 ;
        RECT 232.19 0 232.45 0.26 ;
    END
  END A_DIN[99]
  PIN A_DOUT[99]
    DIRECTION OUTPUT ;
    USE SIGNAL ;
    ANTENNADIFFAREA 0.988 LAYER Metal2 ;
    PORT
      LAYER Metal2 ;
        RECT 233.15 0 233.41 0.26 ;
    END
  END A_DOUT[99]
  PIN A_DIN[100]
    DIRECTION INPUT ;
    USE SIGNAL ;
    ANTENNAMODEL OXIDE1 ;
      ANTENNAGATEAREA 0.20085 LAYER Metal2 ;
    PORT
      LAYER Metal2 ;
        RECT 234.11 0 234.37 0.26 ;
    END
  END A_DIN[100]
  PIN A_DOUT[100]
    DIRECTION OUTPUT ;
    USE SIGNAL ;
    ANTENNADIFFAREA 0.988 LAYER Metal2 ;
    PORT
      LAYER Metal2 ;
        RECT 235.07 0 235.33 0.26 ;
    END
  END A_DOUT[100]
  PIN A_DIN[101]
    DIRECTION INPUT ;
    USE SIGNAL ;
    ANTENNAMODEL OXIDE1 ;
      ANTENNAGATEAREA 0.20085 LAYER Metal2 ;
    PORT
      LAYER Metal2 ;
        RECT 236.03 0 236.29 0.26 ;
    END
  END A_DIN[101]
  PIN A_DOUT[101]
    DIRECTION OUTPUT ;
    USE SIGNAL ;
    ANTENNADIFFAREA 0.988 LAYER Metal2 ;
    PORT
      LAYER Metal2 ;
        RECT 236.99 0 237.25 0.26 ;
    END
  END A_DOUT[101]
  PIN A_DIN[102]
    DIRECTION INPUT ;
    USE SIGNAL ;
    ANTENNAMODEL OXIDE1 ;
      ANTENNAGATEAREA 0.20085 LAYER Metal2 ;
    PORT
      LAYER Metal2 ;
        RECT 237.95 0 238.21 0.26 ;
    END
  END A_DIN[102]
  PIN A_DOUT[102]
    DIRECTION OUTPUT ;
    USE SIGNAL ;
    ANTENNADIFFAREA 0.988 LAYER Metal2 ;
    PORT
      LAYER Metal2 ;
        RECT 238.91 0 239.17 0.26 ;
    END
  END A_DOUT[102]
  PIN A_DIN[103]
    DIRECTION INPUT ;
    USE SIGNAL ;
    ANTENNAMODEL OXIDE1 ;
      ANTENNAGATEAREA 0.20085 LAYER Metal2 ;
    PORT
      LAYER Metal2 ;
        RECT 239.87 0 240.13 0.26 ;
    END
  END A_DIN[103]
  PIN A_DOUT[103]
    DIRECTION OUTPUT ;
    USE SIGNAL ;
    ANTENNADIFFAREA 0.988 LAYER Metal2 ;
    PORT
      LAYER Metal2 ;
        RECT 240.83 0 241.09 0.26 ;
    END
  END A_DOUT[103]
  PIN A_DIN[104]
    DIRECTION INPUT ;
    USE SIGNAL ;
    ANTENNAMODEL OXIDE1 ;
      ANTENNAGATEAREA 0.20085 LAYER Metal2 ;
    PORT
      LAYER Metal2 ;
        RECT 241.79 0 242.05 0.26 ;
    END
  END A_DIN[104]
  PIN A_DOUT[104]
    DIRECTION OUTPUT ;
    USE SIGNAL ;
    ANTENNADIFFAREA 0.988 LAYER Metal2 ;
    PORT
      LAYER Metal2 ;
        RECT 242.75 0 243.01 0.26 ;
    END
  END A_DOUT[104]
  PIN A_DIN[105]
    DIRECTION INPUT ;
    USE SIGNAL ;
    ANTENNAMODEL OXIDE1 ;
      ANTENNAGATEAREA 0.20085 LAYER Metal2 ;
    PORT
      LAYER Metal2 ;
        RECT 243.71 0 243.97 0.26 ;
    END
  END A_DIN[105]
  PIN A_DOUT[105]
    DIRECTION OUTPUT ;
    USE SIGNAL ;
    ANTENNADIFFAREA 0.988 LAYER Metal2 ;
    PORT
      LAYER Metal2 ;
        RECT 244.67 0 244.93 0.26 ;
    END
  END A_DOUT[105]
  PIN A_DIN[106]
    DIRECTION INPUT ;
    USE SIGNAL ;
    ANTENNAMODEL OXIDE1 ;
      ANTENNAGATEAREA 0.20085 LAYER Metal2 ;
    PORT
      LAYER Metal2 ;
        RECT 245.63 0 245.89 0.26 ;
    END
  END A_DIN[106]
  PIN A_DOUT[106]
    DIRECTION OUTPUT ;
    USE SIGNAL ;
    ANTENNADIFFAREA 0.988 LAYER Metal2 ;
    PORT
      LAYER Metal2 ;
        RECT 246.59 0 246.85 0.26 ;
    END
  END A_DOUT[106]
  PIN A_DIN[107]
    DIRECTION INPUT ;
    USE SIGNAL ;
    ANTENNAMODEL OXIDE1 ;
      ANTENNAGATEAREA 0.20085 LAYER Metal2 ;
    PORT
      LAYER Metal2 ;
        RECT 247.55 0 247.81 0.26 ;
    END
  END A_DIN[107]
  PIN A_DOUT[107]
    DIRECTION OUTPUT ;
    USE SIGNAL ;
    ANTENNADIFFAREA 0.988 LAYER Metal2 ;
    PORT
      LAYER Metal2 ;
        RECT 248.51 0 248.77 0.26 ;
    END
  END A_DOUT[107]
  PIN A_DIN[108]
    DIRECTION INPUT ;
    USE SIGNAL ;
    ANTENNAMODEL OXIDE1 ;
      ANTENNAGATEAREA 0.20085 LAYER Metal2 ;
    PORT
      LAYER Metal2 ;
        RECT 249.47 0 249.73 0.26 ;
    END
  END A_DIN[108]
  PIN A_DOUT[108]
    DIRECTION OUTPUT ;
    USE SIGNAL ;
    ANTENNADIFFAREA 0.988 LAYER Metal2 ;
    PORT
      LAYER Metal2 ;
        RECT 250.43 0 250.69 0.26 ;
    END
  END A_DOUT[108]
  PIN A_DIN[109]
    DIRECTION INPUT ;
    USE SIGNAL ;
    ANTENNAMODEL OXIDE1 ;
      ANTENNAGATEAREA 0.20085 LAYER Metal2 ;
    PORT
      LAYER Metal2 ;
        RECT 251.39 0 251.65 0.26 ;
    END
  END A_DIN[109]
  PIN A_DOUT[109]
    DIRECTION OUTPUT ;
    USE SIGNAL ;
    ANTENNADIFFAREA 0.988 LAYER Metal2 ;
    PORT
      LAYER Metal2 ;
        RECT 252.35 0 252.61 0.26 ;
    END
  END A_DOUT[109]
  PIN A_DIN[110]
    DIRECTION INPUT ;
    USE SIGNAL ;
    ANTENNAMODEL OXIDE1 ;
      ANTENNAGATEAREA 0.20085 LAYER Metal2 ;
    PORT
      LAYER Metal2 ;
        RECT 253.31 0 253.57 0.26 ;
    END
  END A_DIN[110]
  PIN A_DOUT[110]
    DIRECTION OUTPUT ;
    USE SIGNAL ;
    ANTENNADIFFAREA 0.988 LAYER Metal2 ;
    PORT
      LAYER Metal2 ;
        RECT 254.27 0 254.53 0.26 ;
    END
  END A_DOUT[110]
  PIN A_DIN[111]
    DIRECTION INPUT ;
    USE SIGNAL ;
    ANTENNAMODEL OXIDE1 ;
      ANTENNAGATEAREA 0.20085 LAYER Metal2 ;
    PORT
      LAYER Metal2 ;
        RECT 255.23 0 255.49 0.26 ;
    END
  END A_DIN[111]
  PIN A_DOUT[111]
    DIRECTION OUTPUT ;
    USE SIGNAL ;
    ANTENNADIFFAREA 0.988 LAYER Metal2 ;
    PORT
      LAYER Metal2 ;
        RECT 256.19 0 256.45 0.26 ;
    END
  END A_DOUT[111]
  PIN A_DIN[112]
    DIRECTION INPUT ;
    USE SIGNAL ;
    ANTENNAMODEL OXIDE1 ;
      ANTENNAGATEAREA 0.20085 LAYER Metal2 ;
    PORT
      LAYER Metal2 ;
        RECT 257.15 0 257.41 0.26 ;
    END
  END A_DIN[112]
  PIN A_DOUT[112]
    DIRECTION OUTPUT ;
    USE SIGNAL ;
    ANTENNADIFFAREA 0.988 LAYER Metal2 ;
    PORT
      LAYER Metal2 ;
        RECT 258.11 0 258.37 0.26 ;
    END
  END A_DOUT[112]
  PIN A_DIN[113]
    DIRECTION INPUT ;
    USE SIGNAL ;
    ANTENNAMODEL OXIDE1 ;
      ANTENNAGATEAREA 0.20085 LAYER Metal2 ;
    PORT
      LAYER Metal2 ;
        RECT 259.07 0 259.33 0.26 ;
    END
  END A_DIN[113]
  PIN A_DOUT[113]
    DIRECTION OUTPUT ;
    USE SIGNAL ;
    ANTENNADIFFAREA 0.988 LAYER Metal2 ;
    PORT
      LAYER Metal2 ;
        RECT 260.03 0 260.29 0.26 ;
    END
  END A_DOUT[113]
  PIN A_DIN[114]
    DIRECTION INPUT ;
    USE SIGNAL ;
    ANTENNAMODEL OXIDE1 ;
      ANTENNAGATEAREA 0.20085 LAYER Metal2 ;
    PORT
      LAYER Metal2 ;
        RECT 260.99 0 261.25 0.26 ;
    END
  END A_DIN[114]
  PIN A_DOUT[114]
    DIRECTION OUTPUT ;
    USE SIGNAL ;
    ANTENNADIFFAREA 0.988 LAYER Metal2 ;
    PORT
      LAYER Metal2 ;
        RECT 261.95 0 262.21 0.26 ;
    END
  END A_DOUT[114]
  PIN A_DIN[115]
    DIRECTION INPUT ;
    USE SIGNAL ;
    ANTENNAMODEL OXIDE1 ;
      ANTENNAGATEAREA 0.20085 LAYER Metal2 ;
    PORT
      LAYER Metal2 ;
        RECT 262.91 0 263.17 0.26 ;
    END
  END A_DIN[115]
  PIN A_DOUT[115]
    DIRECTION OUTPUT ;
    USE SIGNAL ;
    ANTENNADIFFAREA 0.988 LAYER Metal2 ;
    PORT
      LAYER Metal2 ;
        RECT 263.87 0 264.13 0.26 ;
    END
  END A_DOUT[115]
  PIN A_DIN[116]
    DIRECTION INPUT ;
    USE SIGNAL ;
    ANTENNAMODEL OXIDE1 ;
      ANTENNAGATEAREA 0.20085 LAYER Metal2 ;
    PORT
      LAYER Metal2 ;
        RECT 264.83 0 265.09 0.26 ;
    END
  END A_DIN[116]
  PIN A_DOUT[116]
    DIRECTION OUTPUT ;
    USE SIGNAL ;
    ANTENNADIFFAREA 0.988 LAYER Metal2 ;
    PORT
      LAYER Metal2 ;
        RECT 265.79 0 266.05 0.26 ;
    END
  END A_DOUT[116]
  PIN A_DIN[117]
    DIRECTION INPUT ;
    USE SIGNAL ;
    ANTENNAMODEL OXIDE1 ;
      ANTENNAGATEAREA 0.20085 LAYER Metal2 ;
    PORT
      LAYER Metal2 ;
        RECT 266.75 0 267.01 0.26 ;
    END
  END A_DIN[117]
  PIN A_DOUT[117]
    DIRECTION OUTPUT ;
    USE SIGNAL ;
    ANTENNADIFFAREA 0.988 LAYER Metal2 ;
    PORT
      LAYER Metal2 ;
        RECT 267.71 0 267.97 0.26 ;
    END
  END A_DOUT[117]
  PIN A_DIN[118]
    DIRECTION INPUT ;
    USE SIGNAL ;
    ANTENNAMODEL OXIDE1 ;
      ANTENNAGATEAREA 0.20085 LAYER Metal2 ;
    PORT
      LAYER Metal2 ;
        RECT 268.67 0 268.93 0.26 ;
    END
  END A_DIN[118]
  PIN A_DOUT[118]
    DIRECTION OUTPUT ;
    USE SIGNAL ;
    ANTENNADIFFAREA 0.988 LAYER Metal2 ;
    PORT
      LAYER Metal2 ;
        RECT 269.63 0 269.89 0.26 ;
    END
  END A_DOUT[118]
  PIN A_DIN[119]
    DIRECTION INPUT ;
    USE SIGNAL ;
    ANTENNAMODEL OXIDE1 ;
      ANTENNAGATEAREA 0.20085 LAYER Metal2 ;
    PORT
      LAYER Metal2 ;
        RECT 270.59 0 270.85 0.26 ;
    END
  END A_DIN[119]
  PIN A_DOUT[119]
    DIRECTION OUTPUT ;
    USE SIGNAL ;
    ANTENNADIFFAREA 0.988 LAYER Metal2 ;
    PORT
      LAYER Metal2 ;
        RECT 271.55 0 271.81 0.26 ;
    END
  END A_DOUT[119]
  PIN A_DIN[120]
    DIRECTION INPUT ;
    USE SIGNAL ;
    ANTENNAMODEL OXIDE1 ;
      ANTENNAGATEAREA 0.20085 LAYER Metal2 ;
    PORT
      LAYER Metal2 ;
        RECT 272.51 0 272.77 0.26 ;
    END
  END A_DIN[120]
  PIN A_DOUT[120]
    DIRECTION OUTPUT ;
    USE SIGNAL ;
    ANTENNADIFFAREA 0.988 LAYER Metal2 ;
    PORT
      LAYER Metal2 ;
        RECT 273.47 0 273.73 0.26 ;
    END
  END A_DOUT[120]
  PIN A_DIN[121]
    DIRECTION INPUT ;
    USE SIGNAL ;
    ANTENNAMODEL OXIDE1 ;
      ANTENNAGATEAREA 0.20085 LAYER Metal2 ;
    PORT
      LAYER Metal2 ;
        RECT 274.43 0 274.69 0.26 ;
    END
  END A_DIN[121]
  PIN A_DOUT[121]
    DIRECTION OUTPUT ;
    USE SIGNAL ;
    ANTENNADIFFAREA 0.988 LAYER Metal2 ;
    PORT
      LAYER Metal2 ;
        RECT 275.39 0 275.65 0.26 ;
    END
  END A_DOUT[121]
  PIN A_DIN[122]
    DIRECTION INPUT ;
    USE SIGNAL ;
    ANTENNAMODEL OXIDE1 ;
      ANTENNAGATEAREA 0.20085 LAYER Metal2 ;
    PORT
      LAYER Metal2 ;
        RECT 276.35 0 276.61 0.26 ;
    END
  END A_DIN[122]
  PIN A_DOUT[122]
    DIRECTION OUTPUT ;
    USE SIGNAL ;
    ANTENNADIFFAREA 0.988 LAYER Metal2 ;
    PORT
      LAYER Metal2 ;
        RECT 277.31 0 277.57 0.26 ;
    END
  END A_DOUT[122]
  PIN A_DIN[123]
    DIRECTION INPUT ;
    USE SIGNAL ;
    ANTENNAMODEL OXIDE1 ;
      ANTENNAGATEAREA 0.20085 LAYER Metal2 ;
    PORT
      LAYER Metal2 ;
        RECT 278.27 0 278.53 0.26 ;
    END
  END A_DIN[123]
  PIN A_DOUT[123]
    DIRECTION OUTPUT ;
    USE SIGNAL ;
    ANTENNADIFFAREA 0.988 LAYER Metal2 ;
    PORT
      LAYER Metal2 ;
        RECT 279.23 0 279.49 0.26 ;
    END
  END A_DOUT[123]
  PIN A_DIN[124]
    DIRECTION INPUT ;
    USE SIGNAL ;
    ANTENNAMODEL OXIDE1 ;
      ANTENNAGATEAREA 0.20085 LAYER Metal2 ;
    PORT
      LAYER Metal2 ;
        RECT 280.19 0 280.45 0.26 ;
    END
  END A_DIN[124]
  PIN A_DOUT[124]
    DIRECTION OUTPUT ;
    USE SIGNAL ;
    ANTENNADIFFAREA 0.988 LAYER Metal2 ;
    PORT
      LAYER Metal2 ;
        RECT 281.15 0 281.41 0.26 ;
    END
  END A_DOUT[124]
  PIN A_DIN[125]
    DIRECTION INPUT ;
    USE SIGNAL ;
    ANTENNAMODEL OXIDE1 ;
      ANTENNAGATEAREA 0.20085 LAYER Metal2 ;
    PORT
      LAYER Metal2 ;
        RECT 282.11 0 282.37 0.26 ;
    END
  END A_DIN[125]
  PIN A_DOUT[125]
    DIRECTION OUTPUT ;
    USE SIGNAL ;
    ANTENNADIFFAREA 0.988 LAYER Metal2 ;
    PORT
      LAYER Metal2 ;
        RECT 283.07 0 283.33 0.26 ;
    END
  END A_DOUT[125]
  PIN A_DIN[126]
    DIRECTION INPUT ;
    USE SIGNAL ;
    ANTENNAMODEL OXIDE1 ;
      ANTENNAGATEAREA 0.20085 LAYER Metal2 ;
    PORT
      LAYER Metal2 ;
        RECT 284.03 0 284.29 0.26 ;
    END
  END A_DIN[126]
  PIN A_DOUT[126]
    DIRECTION OUTPUT ;
    USE SIGNAL ;
    ANTENNADIFFAREA 0.988 LAYER Metal2 ;
    PORT
      LAYER Metal2 ;
        RECT 284.99 0 285.25 0.26 ;
    END
  END A_DOUT[126]
  PIN A_DIN[127]
    DIRECTION INPUT ;
    USE SIGNAL ;
    ANTENNAMODEL OXIDE1 ;
      ANTENNAGATEAREA 0.20085 LAYER Metal2 ;
    PORT
      LAYER Metal2 ;
        RECT 285.95 0 286.21 0.26 ;
    END
  END A_DIN[127]
  PIN A_DOUT[127]
    DIRECTION OUTPUT ;
    USE SIGNAL ;
    ANTENNADIFFAREA 0.988 LAYER Metal2 ;
    PORT
      LAYER Metal2 ;
        RECT 286.91 0 287.17 0.26 ;
    END
  END A_DOUT[127]
  PIN A_DIN[128]
    DIRECTION INPUT ;
    USE SIGNAL ;
    ANTENNAMODEL OXIDE1 ;
      ANTENNAGATEAREA 0.20085 LAYER Metal2 ;
    PORT
      LAYER Metal2 ;
        RECT 287.87 0 288.13 0.26 ;
    END
  END A_DIN[128]
  PIN A_DOUT[128]
    DIRECTION OUTPUT ;
    USE SIGNAL ;
    ANTENNADIFFAREA 0.988 LAYER Metal2 ;
    PORT
      LAYER Metal2 ;
        RECT 288.83 0 289.09 0.26 ;
    END
  END A_DOUT[128]
  PIN A_DIN[129]
    DIRECTION INPUT ;
    USE SIGNAL ;
    ANTENNAMODEL OXIDE1 ;
      ANTENNAGATEAREA 0.20085 LAYER Metal2 ;
    PORT
      LAYER Metal2 ;
        RECT 289.79 0 290.05 0.26 ;
    END
  END A_DIN[129]
  PIN A_DOUT[129]
    DIRECTION OUTPUT ;
    USE SIGNAL ;
    ANTENNADIFFAREA 0.988 LAYER Metal2 ;
    PORT
      LAYER Metal2 ;
        RECT 290.75 0 291.01 0.26 ;
    END
  END A_DOUT[129]
  PIN A_DIN[130]
    DIRECTION INPUT ;
    USE SIGNAL ;
    ANTENNAMODEL OXIDE1 ;
      ANTENNAGATEAREA 0.20085 LAYER Metal2 ;
    PORT
      LAYER Metal2 ;
        RECT 291.71 0 291.97 0.26 ;
    END
  END A_DIN[130]
  PIN A_DOUT[130]
    DIRECTION OUTPUT ;
    USE SIGNAL ;
    ANTENNADIFFAREA 0.988 LAYER Metal2 ;
    PORT
      LAYER Metal2 ;
        RECT 292.67 0 292.93 0.26 ;
    END
  END A_DOUT[130]
  PIN A_DIN[131]
    DIRECTION INPUT ;
    USE SIGNAL ;
    ANTENNAMODEL OXIDE1 ;
      ANTENNAGATEAREA 0.20085 LAYER Metal2 ;
    PORT
      LAYER Metal2 ;
        RECT 293.63 0 293.89 0.26 ;
    END
  END A_DIN[131]
  PIN A_DOUT[131]
    DIRECTION OUTPUT ;
    USE SIGNAL ;
    ANTENNADIFFAREA 0.988 LAYER Metal2 ;
    PORT
      LAYER Metal2 ;
        RECT 294.59 0 294.85 0.26 ;
    END
  END A_DOUT[131]
  PIN A_DIN[132]
    DIRECTION INPUT ;
    USE SIGNAL ;
    ANTENNAMODEL OXIDE1 ;
      ANTENNAGATEAREA 0.20085 LAYER Metal2 ;
    PORT
      LAYER Metal2 ;
        RECT 295.55 0 295.81 0.26 ;
    END
  END A_DIN[132]
  PIN A_DOUT[132]
    DIRECTION OUTPUT ;
    USE SIGNAL ;
    ANTENNADIFFAREA 0.988 LAYER Metal2 ;
    PORT
      LAYER Metal2 ;
        RECT 296.51 0 296.77 0.26 ;
    END
  END A_DOUT[132]
  PIN A_DIN[133]
    DIRECTION INPUT ;
    USE SIGNAL ;
    ANTENNAMODEL OXIDE1 ;
      ANTENNAGATEAREA 0.20085 LAYER Metal2 ;
    PORT
      LAYER Metal2 ;
        RECT 297.47 0 297.73 0.26 ;
    END
  END A_DIN[133]
  PIN A_DOUT[133]
    DIRECTION OUTPUT ;
    USE SIGNAL ;
    ANTENNADIFFAREA 0.988 LAYER Metal2 ;
    PORT
      LAYER Metal2 ;
        RECT 298.43 0 298.69 0.26 ;
    END
  END A_DOUT[133]
  PIN A_DIN[134]
    DIRECTION INPUT ;
    USE SIGNAL ;
    ANTENNAMODEL OXIDE1 ;
      ANTENNAGATEAREA 0.20085 LAYER Metal2 ;
    PORT
      LAYER Metal2 ;
        RECT 299.39 0 299.65 0.26 ;
    END
  END A_DIN[134]
  PIN A_DOUT[134]
    DIRECTION OUTPUT ;
    USE SIGNAL ;
    ANTENNADIFFAREA 0.988 LAYER Metal2 ;
    PORT
      LAYER Metal2 ;
        RECT 300.35 0 300.61 0.26 ;
    END
  END A_DOUT[134]
  PIN A_DIN[135]
    DIRECTION INPUT ;
    USE SIGNAL ;
    ANTENNAMODEL OXIDE1 ;
      ANTENNAGATEAREA 0.20085 LAYER Metal2 ;
    PORT
      LAYER Metal2 ;
        RECT 301.31 0 301.57 0.26 ;
    END
  END A_DIN[135]
  PIN A_DOUT[135]
    DIRECTION OUTPUT ;
    USE SIGNAL ;
    ANTENNADIFFAREA 0.988 LAYER Metal2 ;
    PORT
      LAYER Metal2 ;
        RECT 302.27 0 302.53 0.26 ;
    END
  END A_DOUT[135]
  PIN A_DIN[136]
    DIRECTION INPUT ;
    USE SIGNAL ;
    ANTENNAMODEL OXIDE1 ;
      ANTENNAGATEAREA 0.20085 LAYER Metal2 ;
    PORT
      LAYER Metal2 ;
        RECT 303.23 0 303.49 0.26 ;
    END
  END A_DIN[136]
  PIN A_DOUT[136]
    DIRECTION OUTPUT ;
    USE SIGNAL ;
    ANTENNADIFFAREA 0.988 LAYER Metal2 ;
    PORT
      LAYER Metal2 ;
        RECT 304.19 0 304.45 0.26 ;
    END
  END A_DOUT[136]
  PIN A_DIN[137]
    DIRECTION INPUT ;
    USE SIGNAL ;
    ANTENNAMODEL OXIDE1 ;
      ANTENNAGATEAREA 0.20085 LAYER Metal2 ;
    PORT
      LAYER Metal2 ;
        RECT 305.15 0 305.41 0.26 ;
    END
  END A_DIN[137]
  PIN A_DOUT[137]
    DIRECTION OUTPUT ;
    USE SIGNAL ;
    ANTENNADIFFAREA 0.988 LAYER Metal2 ;
    PORT
      LAYER Metal2 ;
        RECT 306.11 0 306.37 0.26 ;
    END
  END A_DOUT[137]
  PIN A_DIN[138]
    DIRECTION INPUT ;
    USE SIGNAL ;
    ANTENNAMODEL OXIDE1 ;
      ANTENNAGATEAREA 0.20085 LAYER Metal2 ;
    PORT
      LAYER Metal2 ;
        RECT 307.07 0 307.33 0.26 ;
    END
  END A_DIN[138]
  PIN A_DOUT[138]
    DIRECTION OUTPUT ;
    USE SIGNAL ;
    ANTENNADIFFAREA 0.988 LAYER Metal2 ;
    PORT
      LAYER Metal2 ;
        RECT 308.03 0 308.29 0.26 ;
    END
  END A_DOUT[138]
  PIN A_DIN[139]
    DIRECTION INPUT ;
    USE SIGNAL ;
    ANTENNAMODEL OXIDE1 ;
      ANTENNAGATEAREA 0.20085 LAYER Metal2 ;
    PORT
      LAYER Metal2 ;
        RECT 308.99 0 309.25 0.26 ;
    END
  END A_DIN[139]
  PIN A_DOUT[139]
    DIRECTION OUTPUT ;
    USE SIGNAL ;
    ANTENNADIFFAREA 0.988 LAYER Metal2 ;
    PORT
      LAYER Metal2 ;
        RECT 309.95 0 310.21 0.26 ;
    END
  END A_DOUT[139]
  PIN A_DIN[140]
    DIRECTION INPUT ;
    USE SIGNAL ;
    ANTENNAMODEL OXIDE1 ;
      ANTENNAGATEAREA 0.20085 LAYER Metal2 ;
    PORT
      LAYER Metal2 ;
        RECT 310.91 0 311.17 0.26 ;
    END
  END A_DIN[140]
  PIN A_DOUT[140]
    DIRECTION OUTPUT ;
    USE SIGNAL ;
    ANTENNADIFFAREA 0.988 LAYER Metal2 ;
    PORT
      LAYER Metal2 ;
        RECT 311.87 0 312.13 0.26 ;
    END
  END A_DOUT[140]
  PIN A_DIN[141]
    DIRECTION INPUT ;
    USE SIGNAL ;
    ANTENNAMODEL OXIDE1 ;
      ANTENNAGATEAREA 0.20085 LAYER Metal2 ;
    PORT
      LAYER Metal2 ;
        RECT 312.83 0 313.09 0.26 ;
    END
  END A_DIN[141]
  PIN A_DOUT[141]
    DIRECTION OUTPUT ;
    USE SIGNAL ;
    ANTENNADIFFAREA 0.988 LAYER Metal2 ;
    PORT
      LAYER Metal2 ;
        RECT 313.79 0 314.05 0.26 ;
    END
  END A_DOUT[141]
  PIN A_DIN[142]
    DIRECTION INPUT ;
    USE SIGNAL ;
    ANTENNAMODEL OXIDE1 ;
      ANTENNAGATEAREA 0.20085 LAYER Metal2 ;
    PORT
      LAYER Metal2 ;
        RECT 314.75 0 315.01 0.26 ;
    END
  END A_DIN[142]
  PIN A_DOUT[142]
    DIRECTION OUTPUT ;
    USE SIGNAL ;
    ANTENNADIFFAREA 0.988 LAYER Metal2 ;
    PORT
      LAYER Metal2 ;
        RECT 315.71 0 315.97 0.26 ;
    END
  END A_DOUT[142]
  PIN A_DIN[143]
    DIRECTION INPUT ;
    USE SIGNAL ;
    ANTENNAMODEL OXIDE1 ;
      ANTENNAGATEAREA 0.20085 LAYER Metal2 ;
    PORT
      LAYER Metal2 ;
        RECT 316.67 0 316.93 0.26 ;
    END
  END A_DIN[143]
  PIN A_DOUT[143]
    DIRECTION OUTPUT ;
    USE SIGNAL ;
    ANTENNADIFFAREA 0.988 LAYER Metal2 ;
    PORT
      LAYER Metal2 ;
        RECT 317.63 0 317.89 0.26 ;
    END
  END A_DOUT[143]
  PIN VDD
    DIRECTION INOUT ;
    USE POWER ;
    PORT
      LAYER Metal4 ;
        RECT 15.5 0 18.31 30.425 ;
    END
    PORT
      LAYER Metal4 ;
        RECT 26.74 0 29.55 30.425 ;
    END
    PORT
      LAYER Metal4 ;
        RECT 37.98 0 40.79 30.425 ;
    END
    PORT
      LAYER Metal4 ;
        RECT 49.22 0 52.03 30.425 ;
    END
    PORT
      LAYER Metal4 ;
        RECT 60.46 0 63.27 30.425 ;
    END
    PORT
      LAYER Metal4 ;
        RECT 71.7 0 74.51 30.425 ;
    END
    PORT
      LAYER Metal4 ;
        RECT 82.94 0 85.75 30.425 ;
    END
    PORT
      LAYER Metal4 ;
        RECT 94.18 0 96.99 30.425 ;
    END
    PORT
      LAYER Metal4 ;
        RECT 105.42 0 108.23 30.425 ;
    END
    PORT
      LAYER Metal4 ;
        RECT 116.66 0 119.47 30.425 ;
    END
    PORT
      LAYER Metal4 ;
        RECT 127.9 0 130.71 30.425 ;
    END
    PORT
      LAYER Metal4 ;
        RECT 139.14 0 141.95 30.425 ;
    END
    PORT
      LAYER Metal4 ;
        RECT 150.38 0 153.19 30.425 ;
    END
    PORT
      LAYER Metal4 ;
        RECT 161.62 0 164.43 30.425 ;
    END
    PORT
      LAYER Metal4 ;
        RECT 172.86 0 175.67 30.425 ;
    END
    PORT
      LAYER Metal4 ;
        RECT 184.1 0 186.91 30.425 ;
    END
    PORT
      LAYER Metal4 ;
        RECT 195.34 0 198.15 30.425 ;
    END
    PORT
      LAYER Metal4 ;
        RECT 206.58 0 209.39 30.425 ;
    END
    PORT
      LAYER Metal4 ;
        RECT 217.82 0 220.63 30.425 ;
    END
    PORT
      LAYER Metal4 ;
        RECT 229.06 0 231.87 30.425 ;
    END
    PORT
      LAYER Metal4 ;
        RECT 240.3 0 243.11 30.425 ;
    END
    PORT
      LAYER Metal4 ;
        RECT 251.54 0 254.35 30.425 ;
    END
    PORT
      LAYER Metal4 ;
        RECT 262.78 0 265.59 30.425 ;
    END
    PORT
      LAYER Metal4 ;
        RECT 274.02 0 276.83 30.425 ;
    END
    PORT
      LAYER Metal4 ;
        RECT 285.26 0 288.07 30.425 ;
    END
    PORT
      LAYER Metal4 ;
        RECT 296.5 0 299.31 30.425 ;
    END
    PORT
      LAYER Metal4 ;
        RECT 307.74 0 310.55 30.425 ;
    END
    PORT
      LAYER Metal4 ;
        RECT 318.98 0 321.79 30.425 ;
    END
  END VDD
  PIN VDDARRAY
    DIRECTION INOUT ;
    USE POWER ;
    PORT
      LAYER Metal4 ;
        RECT 15.5 37.065 18.31 347.76 ;
    END
    PORT
      LAYER Metal4 ;
        RECT 26.74 37.065 29.55 347.76 ;
    END
    PORT
      LAYER Metal4 ;
        RECT 37.98 37.065 40.79 347.76 ;
    END
    PORT
      LAYER Metal4 ;
        RECT 49.22 37.065 52.03 347.76 ;
    END
    PORT
      LAYER Metal4 ;
        RECT 60.46 37.065 63.27 347.76 ;
    END
    PORT
      LAYER Metal4 ;
        RECT 71.7 37.065 74.51 347.76 ;
    END
    PORT
      LAYER Metal4 ;
        RECT 82.94 37.065 85.75 347.76 ;
    END
    PORT
      LAYER Metal4 ;
        RECT 94.18 37.065 96.99 347.76 ;
    END
    PORT
      LAYER Metal4 ;
        RECT 105.42 37.065 108.23 347.76 ;
    END
    PORT
      LAYER Metal4 ;
        RECT 116.66 37.065 119.47 347.76 ;
    END
    PORT
      LAYER Metal4 ;
        RECT 127.9 37.065 130.71 347.76 ;
    END
    PORT
      LAYER Metal4 ;
        RECT 139.14 37.065 141.95 347.76 ;
    END
    PORT
      LAYER Metal4 ;
        RECT 150.38 37.065 153.19 347.76 ;
    END
    PORT
      LAYER Metal4 ;
        RECT 161.62 37.065 164.43 347.76 ;
    END
    PORT
      LAYER Metal4 ;
        RECT 172.86 37.065 175.67 347.76 ;
    END
    PORT
      LAYER Metal4 ;
        RECT 184.1 37.065 186.91 347.76 ;
    END
    PORT
      LAYER Metal4 ;
        RECT 195.34 37.065 198.15 347.76 ;
    END
    PORT
      LAYER Metal4 ;
        RECT 206.58 37.065 209.39 347.76 ;
    END
    PORT
      LAYER Metal4 ;
        RECT 217.82 37.065 220.63 347.76 ;
    END
    PORT
      LAYER Metal4 ;
        RECT 229.06 37.065 231.87 347.76 ;
    END
    PORT
      LAYER Metal4 ;
        RECT 240.3 37.065 243.11 347.76 ;
    END
    PORT
      LAYER Metal4 ;
        RECT 251.54 37.065 254.35 347.76 ;
    END
    PORT
      LAYER Metal4 ;
        RECT 262.78 37.065 265.59 347.76 ;
    END
    PORT
      LAYER Metal4 ;
        RECT 274.02 37.065 276.83 347.76 ;
    END
    PORT
      LAYER Metal4 ;
        RECT 285.26 37.065 288.07 347.76 ;
    END
    PORT
      LAYER Metal4 ;
        RECT 296.5 37.065 299.31 347.76 ;
    END
    PORT
      LAYER Metal4 ;
        RECT 307.74 37.065 310.55 347.76 ;
    END
    PORT
      LAYER Metal4 ;
        RECT 318.98 37.065 321.79 347.76 ;
    END
  END VDDARRAY
  PIN VSS
    DIRECTION INOUT ;
    USE GROUND ;
    PORT
      LAYER Metal4 ;
        RECT 21.12 0 23.93 347.76 ;
    END
    PORT
      LAYER Metal4 ;
        RECT 32.36 0 35.17 347.76 ;
    END
    PORT
      LAYER Metal4 ;
        RECT 43.6 0 46.41 347.76 ;
    END
    PORT
      LAYER Metal4 ;
        RECT 54.84 0 57.65 347.76 ;
    END
    PORT
      LAYER Metal4 ;
        RECT 66.08 0 68.89 347.76 ;
    END
    PORT
      LAYER Metal4 ;
        RECT 77.32 0 80.13 347.76 ;
    END
    PORT
      LAYER Metal4 ;
        RECT 88.56 0 91.37 347.76 ;
    END
    PORT
      LAYER Metal4 ;
        RECT 99.8 0 102.61 347.76 ;
    END
    PORT
      LAYER Metal4 ;
        RECT 111.04 0 113.85 347.76 ;
    END
    PORT
      LAYER Metal4 ;
        RECT 122.28 0 125.09 347.76 ;
    END
    PORT
      LAYER Metal4 ;
        RECT 133.52 0 136.33 347.76 ;
    END
    PORT
      LAYER Metal4 ;
        RECT 144.76 0 147.57 347.76 ;
    END
    PORT
      LAYER Metal4 ;
        RECT 156 0 158.81 347.76 ;
    END
    PORT
      LAYER Metal4 ;
        RECT 167.24 0 170.05 347.76 ;
    END
    PORT
      LAYER Metal4 ;
        RECT 178.48 0 181.29 347.76 ;
    END
    PORT
      LAYER Metal4 ;
        RECT 189.72 0 192.53 347.76 ;
    END
    PORT
      LAYER Metal4 ;
        RECT 200.96 0 203.77 347.76 ;
    END
    PORT
      LAYER Metal4 ;
        RECT 212.2 0 215.01 347.76 ;
    END
    PORT
      LAYER Metal4 ;
        RECT 223.44 0 226.25 347.76 ;
    END
    PORT
      LAYER Metal4 ;
        RECT 234.68 0 237.49 347.76 ;
    END
    PORT
      LAYER Metal4 ;
        RECT 245.92 0 248.73 347.76 ;
    END
    PORT
      LAYER Metal4 ;
        RECT 257.16 0 259.97 347.76 ;
    END
    PORT
      LAYER Metal4 ;
        RECT 268.4 0 271.21 347.76 ;
    END
    PORT
      LAYER Metal4 ;
        RECT 279.64 0 282.45 347.76 ;
    END
    PORT
      LAYER Metal4 ;
        RECT 290.88 0 293.69 347.76 ;
    END
    PORT
      LAYER Metal4 ;
        RECT 302.12 0 304.93 347.76 ;
    END
    PORT
      LAYER Metal4 ;
        RECT 313.36 0 316.17 347.76 ;
    END
    PORT
      LAYER Metal4 ;
        RECT 324.6 0 327.41 347.76 ;
    END
  END VSS
  OBS
    LAYER Metal1 ;
      RECT 0 0 347.52 347.76 ;
    LAYER Metal2 ;
      RECT 0 1 347.52 347.76 ;
    LAYER Metal3 ;
      RECT 0 1 347.52 347.76 ;
  END
END IHPSG13_SYNTHETIC_RRAM_1P_256x144

END LIBRARY
